VERSION 5.8 ;
BUSBITCHARS "[]" ;
DIVIDERCHAR "/" ;
UNITS
    DATABASE MICRONS 1000 ;
END UNITS

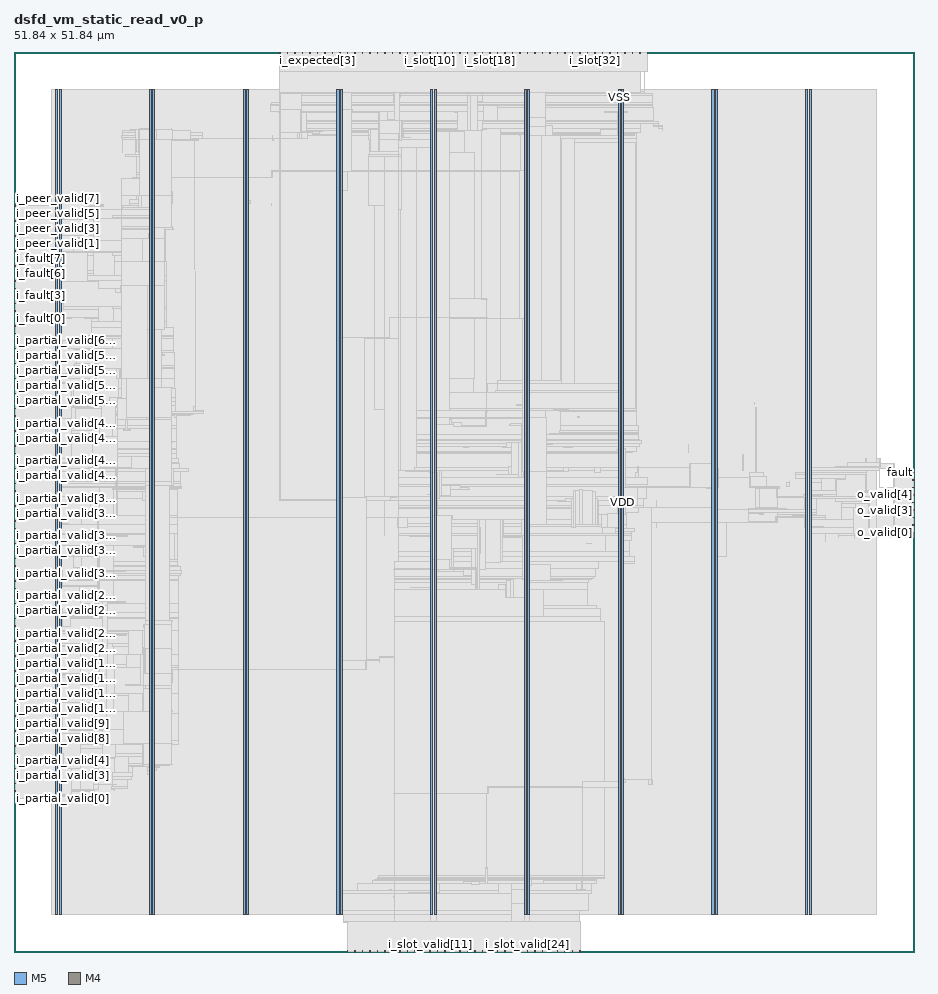
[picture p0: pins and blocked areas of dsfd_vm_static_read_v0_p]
MACRO dsfd_vm_static_read_v0_p
  FOREIGN dsfd_vm_static_read_v0_p 0 0 ;
  CLASS BLOCK ;
  SIZE 51.84 BY 51.84 ;
  PIN ck
    DIRECTION INPUT ;
    USE SIGNAL ;
    PORT
      LAYER M5 ;
        RECT  15.312 51.756 15.336 51.84 ;
    END
  END ck
  PIN fault
    DIRECTION OUTPUT ;
    USE SIGNAL ;
    PORT
      LAYER M4 ;
        RECT  51.756 27.6 51.84 27.624 ;
    END
  END fault
  PIN i_expected[0]
    DIRECTION INPUT ;
    USE SIGNAL ;
    PORT
      LAYER M5 ;
        RECT  16.176 51.756 16.2 51.84 ;
    END
  END i_expected[0]
  PIN i_expected[1]
    DIRECTION INPUT ;
    USE SIGNAL ;
    PORT
      LAYER M5 ;
        RECT  16.608 51.756 16.632 51.84 ;
    END
  END i_expected[1]
  PIN i_expected[2]
    DIRECTION INPUT ;
    USE SIGNAL ;
    PORT
      LAYER M5 ;
        RECT  17.04 51.756 17.064 51.84 ;
    END
  END i_expected[2]
  PIN i_expected[3]
    DIRECTION INPUT ;
    USE SIGNAL ;
    PORT
      LAYER M5 ;
        RECT  17.472 51.756 17.496 51.84 ;
    END
  END i_expected[3]
  PIN i_expected[4]
    DIRECTION INPUT ;
    USE SIGNAL ;
    PORT
      LAYER M5 ;
        RECT  17.904 51.756 17.928 51.84 ;
    END
  END i_expected[4]
  PIN i_expected[5]
    DIRECTION INPUT ;
    USE SIGNAL ;
    PORT
      LAYER M5 ;
        RECT  18.336 51.756 18.36 51.84 ;
    END
  END i_expected[5]
  PIN i_expected[6]
    DIRECTION INPUT ;
    USE SIGNAL ;
    PORT
      LAYER M5 ;
        RECT  18.768 51.756 18.792 51.84 ;
    END
  END i_expected[6]
  PIN i_expected[7]
    DIRECTION INPUT ;
    USE SIGNAL ;
    PORT
      LAYER M5 ;
        RECT  19.2 51.756 19.224 51.84 ;
    END
  END i_expected[7]
  PIN i_fault[0]
    DIRECTION INPUT ;
    USE SIGNAL ;
    PORT
      LAYER M4 ;
        RECT  0 36.48 0.084 36.504 ;
    END
  END i_fault[0]
  PIN i_fault[1]
    DIRECTION INPUT ;
    USE SIGNAL ;
    PORT
      LAYER M4 ;
        RECT  0 36.912 0.084 36.936 ;
    END
  END i_fault[1]
  PIN i_fault[2]
    DIRECTION INPUT ;
    USE SIGNAL ;
    PORT
      LAYER M4 ;
        RECT  0 37.344 0.084 37.368 ;
    END
  END i_fault[2]
  PIN i_fault[3]
    DIRECTION INPUT ;
    USE SIGNAL ;
    PORT
      LAYER M4 ;
        RECT  0 37.776 0.084 37.8 ;
    END
  END i_fault[3]
  PIN i_fault[4]
    DIRECTION INPUT ;
    USE SIGNAL ;
    PORT
      LAYER M4 ;
        RECT  0 38.208 0.084 38.232 ;
    END
  END i_fault[4]
  PIN i_fault[5]
    DIRECTION INPUT ;
    USE SIGNAL ;
    PORT
      LAYER M4 ;
        RECT  0 38.64 0.084 38.664 ;
    END
  END i_fault[5]
  PIN i_fault[6]
    DIRECTION INPUT ;
    USE SIGNAL ;
    PORT
      LAYER M4 ;
        RECT  0 39.072 0.084 39.096 ;
    END
  END i_fault[6]
  PIN i_fault[7]
    DIRECTION INPUT ;
    USE SIGNAL ;
    PORT
      LAYER M4 ;
        RECT  0 39.504 0.084 39.528 ;
    END
  END i_fault[7]
  PIN i_partial_valid[0]
    DIRECTION INPUT ;
    USE SIGNAL ;
    PORT
      LAYER M4 ;
        RECT  0 8.832 0.084 8.856 ;
    END
  END i_partial_valid[0]
  PIN i_partial_valid[10]
    DIRECTION INPUT ;
    USE SIGNAL ;
    PORT
      LAYER M4 ;
        RECT  0 13.152 0.084 13.176 ;
    END
  END i_partial_valid[10]
  PIN i_partial_valid[11]
    DIRECTION INPUT ;
    USE SIGNAL ;
    PORT
      LAYER M4 ;
        RECT  0 13.584 0.084 13.608 ;
    END
  END i_partial_valid[11]
  PIN i_partial_valid[12]
    DIRECTION INPUT ;
    USE SIGNAL ;
    PORT
      LAYER M4 ;
        RECT  0 14.016 0.084 14.04 ;
    END
  END i_partial_valid[12]
  PIN i_partial_valid[13]
    DIRECTION INPUT ;
    USE SIGNAL ;
    PORT
      LAYER M4 ;
        RECT  0 14.448 0.084 14.472 ;
    END
  END i_partial_valid[13]
  PIN i_partial_valid[14]
    DIRECTION INPUT ;
    USE SIGNAL ;
    PORT
      LAYER M4 ;
        RECT  0 14.88 0.084 14.904 ;
    END
  END i_partial_valid[14]
  PIN i_partial_valid[15]
    DIRECTION INPUT ;
    USE SIGNAL ;
    PORT
      LAYER M4 ;
        RECT  0 15.312 0.084 15.336 ;
    END
  END i_partial_valid[15]
  PIN i_partial_valid[16]
    DIRECTION INPUT ;
    USE SIGNAL ;
    PORT
      LAYER M4 ;
        RECT  0 15.744 0.084 15.768 ;
    END
  END i_partial_valid[16]
  PIN i_partial_valid[17]
    DIRECTION INPUT ;
    USE SIGNAL ;
    PORT
      LAYER M4 ;
        RECT  0 16.176 0.084 16.2 ;
    END
  END i_partial_valid[17]
  PIN i_partial_valid[18]
    DIRECTION INPUT ;
    USE SIGNAL ;
    PORT
      LAYER M4 ;
        RECT  0 16.608 0.084 16.632 ;
    END
  END i_partial_valid[18]
  PIN i_partial_valid[19]
    DIRECTION INPUT ;
    USE SIGNAL ;
    PORT
      LAYER M4 ;
        RECT  0 17.04 0.084 17.064 ;
    END
  END i_partial_valid[19]
  PIN i_partial_valid[1]
    DIRECTION INPUT ;
    USE SIGNAL ;
    PORT
      LAYER M4 ;
        RECT  0 9.264 0.084 9.288 ;
    END
  END i_partial_valid[1]
  PIN i_partial_valid[20]
    DIRECTION INPUT ;
    USE SIGNAL ;
    PORT
      LAYER M4 ;
        RECT  0 17.472 0.084 17.496 ;
    END
  END i_partial_valid[20]
  PIN i_partial_valid[21]
    DIRECTION INPUT ;
    USE SIGNAL ;
    PORT
      LAYER M4 ;
        RECT  0 17.904 0.084 17.928 ;
    END
  END i_partial_valid[21]
  PIN i_partial_valid[22]
    DIRECTION INPUT ;
    USE SIGNAL ;
    PORT
      LAYER M4 ;
        RECT  0 18.336 0.084 18.36 ;
    END
  END i_partial_valid[22]
  PIN i_partial_valid[23]
    DIRECTION INPUT ;
    USE SIGNAL ;
    PORT
      LAYER M4 ;
        RECT  0 18.768 0.084 18.792 ;
    END
  END i_partial_valid[23]
  PIN i_partial_valid[24]
    DIRECTION INPUT ;
    USE SIGNAL ;
    PORT
      LAYER M4 ;
        RECT  0 19.2 0.084 19.224 ;
    END
  END i_partial_valid[24]
  PIN i_partial_valid[25]
    DIRECTION INPUT ;
    USE SIGNAL ;
    PORT
      LAYER M4 ;
        RECT  0 19.632 0.084 19.656 ;
    END
  END i_partial_valid[25]
  PIN i_partial_valid[26]
    DIRECTION INPUT ;
    USE SIGNAL ;
    PORT
      LAYER M4 ;
        RECT  0 20.064 0.084 20.088 ;
    END
  END i_partial_valid[26]
  PIN i_partial_valid[27]
    DIRECTION INPUT ;
    USE SIGNAL ;
    PORT
      LAYER M4 ;
        RECT  0 20.496 0.084 20.52 ;
    END
  END i_partial_valid[27]
  PIN i_partial_valid[28]
    DIRECTION INPUT ;
    USE SIGNAL ;
    PORT
      LAYER M4 ;
        RECT  0 20.928 0.084 20.952 ;
    END
  END i_partial_valid[28]
  PIN i_partial_valid[29]
    DIRECTION INPUT ;
    USE SIGNAL ;
    PORT
      LAYER M4 ;
        RECT  0 21.36 0.084 21.384 ;
    END
  END i_partial_valid[29]
  PIN i_partial_valid[2]
    DIRECTION INPUT ;
    USE SIGNAL ;
    PORT
      LAYER M4 ;
        RECT  0 9.696 0.084 9.72 ;
    END
  END i_partial_valid[2]
  PIN i_partial_valid[30]
    DIRECTION INPUT ;
    USE SIGNAL ;
    PORT
      LAYER M4 ;
        RECT  0 21.792 0.084 21.816 ;
    END
  END i_partial_valid[30]
  PIN i_partial_valid[31]
    DIRECTION INPUT ;
    USE SIGNAL ;
    PORT
      LAYER M4 ;
        RECT  0 22.224 0.084 22.248 ;
    END
  END i_partial_valid[31]
  PIN i_partial_valid[32]
    DIRECTION INPUT ;
    USE SIGNAL ;
    PORT
      LAYER M4 ;
        RECT  0 22.656 0.084 22.68 ;
    END
  END i_partial_valid[32]
  PIN i_partial_valid[33]
    DIRECTION INPUT ;
    USE SIGNAL ;
    PORT
      LAYER M4 ;
        RECT  0 23.088 0.084 23.112 ;
    END
  END i_partial_valid[33]
  PIN i_partial_valid[34]
    DIRECTION INPUT ;
    USE SIGNAL ;
    PORT
      LAYER M4 ;
        RECT  0 23.52 0.084 23.544 ;
    END
  END i_partial_valid[34]
  PIN i_partial_valid[35]
    DIRECTION INPUT ;
    USE SIGNAL ;
    PORT
      LAYER M4 ;
        RECT  0 23.952 0.084 23.976 ;
    END
  END i_partial_valid[35]
  PIN i_partial_valid[36]
    DIRECTION INPUT ;
    USE SIGNAL ;
    PORT
      LAYER M4 ;
        RECT  0 24.384 0.084 24.408 ;
    END
  END i_partial_valid[36]
  PIN i_partial_valid[37]
    DIRECTION INPUT ;
    USE SIGNAL ;
    PORT
      LAYER M4 ;
        RECT  0 24.816 0.084 24.84 ;
    END
  END i_partial_valid[37]
  PIN i_partial_valid[38]
    DIRECTION INPUT ;
    USE SIGNAL ;
    PORT
      LAYER M4 ;
        RECT  0 25.248 0.084 25.272 ;
    END
  END i_partial_valid[38]
  PIN i_partial_valid[39]
    DIRECTION INPUT ;
    USE SIGNAL ;
    PORT
      LAYER M4 ;
        RECT  0 25.68 0.084 25.704 ;
    END
  END i_partial_valid[39]
  PIN i_partial_valid[3]
    DIRECTION INPUT ;
    USE SIGNAL ;
    PORT
      LAYER M4 ;
        RECT  0 10.128 0.084 10.152 ;
    END
  END i_partial_valid[3]
  PIN i_partial_valid[40]
    DIRECTION INPUT ;
    USE SIGNAL ;
    PORT
      LAYER M4 ;
        RECT  0 26.112 0.084 26.136 ;
    END
  END i_partial_valid[40]
  PIN i_partial_valid[41]
    DIRECTION INPUT ;
    USE SIGNAL ;
    PORT
      LAYER M4 ;
        RECT  0 26.544 0.084 26.568 ;
    END
  END i_partial_valid[41]
  PIN i_partial_valid[42]
    DIRECTION INPUT ;
    USE SIGNAL ;
    PORT
      LAYER M4 ;
        RECT  0 26.976 0.084 27 ;
    END
  END i_partial_valid[42]
  PIN i_partial_valid[43]
    DIRECTION INPUT ;
    USE SIGNAL ;
    PORT
      LAYER M4 ;
        RECT  0 27.408 0.084 27.432 ;
    END
  END i_partial_valid[43]
  PIN i_partial_valid[44]
    DIRECTION INPUT ;
    USE SIGNAL ;
    PORT
      LAYER M4 ;
        RECT  0 27.84 0.084 27.864 ;
    END
  END i_partial_valid[44]
  PIN i_partial_valid[45]
    DIRECTION INPUT ;
    USE SIGNAL ;
    PORT
      LAYER M4 ;
        RECT  0 28.272 0.084 28.296 ;
    END
  END i_partial_valid[45]
  PIN i_partial_valid[46]
    DIRECTION INPUT ;
    USE SIGNAL ;
    PORT
      LAYER M4 ;
        RECT  0 28.704 0.084 28.728 ;
    END
  END i_partial_valid[46]
  PIN i_partial_valid[47]
    DIRECTION INPUT ;
    USE SIGNAL ;
    PORT
      LAYER M4 ;
        RECT  0 29.136 0.084 29.16 ;
    END
  END i_partial_valid[47]
  PIN i_partial_valid[48]
    DIRECTION INPUT ;
    USE SIGNAL ;
    PORT
      LAYER M4 ;
        RECT  0 29.568 0.084 29.592 ;
    END
  END i_partial_valid[48]
  PIN i_partial_valid[49]
    DIRECTION INPUT ;
    USE SIGNAL ;
    PORT
      LAYER M4 ;
        RECT  0 30 0.084 30.024 ;
    END
  END i_partial_valid[49]
  PIN i_partial_valid[4]
    DIRECTION INPUT ;
    USE SIGNAL ;
    PORT
      LAYER M4 ;
        RECT  0 10.56 0.084 10.584 ;
    END
  END i_partial_valid[4]
  PIN i_partial_valid[50]
    DIRECTION INPUT ;
    USE SIGNAL ;
    PORT
      LAYER M4 ;
        RECT  0 30.432 0.084 30.456 ;
    END
  END i_partial_valid[50]
  PIN i_partial_valid[51]
    DIRECTION INPUT ;
    USE SIGNAL ;
    PORT
      LAYER M4 ;
        RECT  0 30.864 0.084 30.888 ;
    END
  END i_partial_valid[51]
  PIN i_partial_valid[52]
    DIRECTION INPUT ;
    USE SIGNAL ;
    PORT
      LAYER M4 ;
        RECT  0 31.296 0.084 31.32 ;
    END
  END i_partial_valid[52]
  PIN i_partial_valid[53]
    DIRECTION INPUT ;
    USE SIGNAL ;
    PORT
      LAYER M4 ;
        RECT  0 31.728 0.084 31.752 ;
    END
  END i_partial_valid[53]
  PIN i_partial_valid[54]
    DIRECTION INPUT ;
    USE SIGNAL ;
    PORT
      LAYER M4 ;
        RECT  0 32.16 0.084 32.184 ;
    END
  END i_partial_valid[54]
  PIN i_partial_valid[55]
    DIRECTION INPUT ;
    USE SIGNAL ;
    PORT
      LAYER M4 ;
        RECT  0 32.592 0.084 32.616 ;
    END
  END i_partial_valid[55]
  PIN i_partial_valid[56]
    DIRECTION INPUT ;
    USE SIGNAL ;
    PORT
      LAYER M4 ;
        RECT  0 33.024 0.084 33.048 ;
    END
  END i_partial_valid[56]
  PIN i_partial_valid[57]
    DIRECTION INPUT ;
    USE SIGNAL ;
    PORT
      LAYER M4 ;
        RECT  0 33.456 0.084 33.48 ;
    END
  END i_partial_valid[57]
  PIN i_partial_valid[58]
    DIRECTION INPUT ;
    USE SIGNAL ;
    PORT
      LAYER M4 ;
        RECT  0 33.888 0.084 33.912 ;
    END
  END i_partial_valid[58]
  PIN i_partial_valid[59]
    DIRECTION INPUT ;
    USE SIGNAL ;
    PORT
      LAYER M4 ;
        RECT  0 34.32 0.084 34.344 ;
    END
  END i_partial_valid[59]
  PIN i_partial_valid[5]
    DIRECTION INPUT ;
    USE SIGNAL ;
    PORT
      LAYER M4 ;
        RECT  0 10.992 0.084 11.016 ;
    END
  END i_partial_valid[5]
  PIN i_partial_valid[60]
    DIRECTION INPUT ;
    USE SIGNAL ;
    PORT
      LAYER M4 ;
        RECT  0 34.752 0.084 34.776 ;
    END
  END i_partial_valid[60]
  PIN i_partial_valid[61]
    DIRECTION INPUT ;
    USE SIGNAL ;
    PORT
      LAYER M4 ;
        RECT  0 35.184 0.084 35.208 ;
    END
  END i_partial_valid[61]
  PIN i_partial_valid[62]
    DIRECTION INPUT ;
    USE SIGNAL ;
    PORT
      LAYER M4 ;
        RECT  0 35.616 0.084 35.64 ;
    END
  END i_partial_valid[62]
  PIN i_partial_valid[63]
    DIRECTION INPUT ;
    USE SIGNAL ;
    PORT
      LAYER M4 ;
        RECT  0 36.048 0.084 36.072 ;
    END
  END i_partial_valid[63]
  PIN i_partial_valid[6]
    DIRECTION INPUT ;
    USE SIGNAL ;
    PORT
      LAYER M4 ;
        RECT  0 11.424 0.084 11.448 ;
    END
  END i_partial_valid[6]
  PIN i_partial_valid[7]
    DIRECTION INPUT ;
    USE SIGNAL ;
    PORT
      LAYER M4 ;
        RECT  0 11.856 0.084 11.88 ;
    END
  END i_partial_valid[7]
  PIN i_partial_valid[8]
    DIRECTION INPUT ;
    USE SIGNAL ;
    PORT
      LAYER M4 ;
        RECT  0 12.288 0.084 12.312 ;
    END
  END i_partial_valid[8]
  PIN i_partial_valid[9]
    DIRECTION INPUT ;
    USE SIGNAL ;
    PORT
      LAYER M4 ;
        RECT  0 12.72 0.084 12.744 ;
    END
  END i_partial_valid[9]
  PIN i_peer_valid[0]
    DIRECTION INPUT ;
    USE SIGNAL ;
    PORT
      LAYER M4 ;
        RECT  0 39.936 0.084 39.96 ;
    END
  END i_peer_valid[0]
  PIN i_peer_valid[1]
    DIRECTION INPUT ;
    USE SIGNAL ;
    PORT
      LAYER M4 ;
        RECT  0 40.368 0.084 40.392 ;
    END
  END i_peer_valid[1]
  PIN i_peer_valid[2]
    DIRECTION INPUT ;
    USE SIGNAL ;
    PORT
      LAYER M4 ;
        RECT  0 40.8 0.084 40.824 ;
    END
  END i_peer_valid[2]
  PIN i_peer_valid[3]
    DIRECTION INPUT ;
    USE SIGNAL ;
    PORT
      LAYER M4 ;
        RECT  0 41.232 0.084 41.256 ;
    END
  END i_peer_valid[3]
  PIN i_peer_valid[4]
    DIRECTION INPUT ;
    USE SIGNAL ;
    PORT
      LAYER M4 ;
        RECT  0 41.664 0.084 41.688 ;
    END
  END i_peer_valid[4]
  PIN i_peer_valid[5]
    DIRECTION INPUT ;
    USE SIGNAL ;
    PORT
      LAYER M4 ;
        RECT  0 42.096 0.084 42.12 ;
    END
  END i_peer_valid[5]
  PIN i_peer_valid[6]
    DIRECTION INPUT ;
    USE SIGNAL ;
    PORT
      LAYER M4 ;
        RECT  0 42.528 0.084 42.552 ;
    END
  END i_peer_valid[6]
  PIN i_peer_valid[7]
    DIRECTION INPUT ;
    USE SIGNAL ;
    PORT
      LAYER M4 ;
        RECT  0 42.96 0.084 42.984 ;
    END
  END i_peer_valid[7]
  PIN i_slot[0]
    DIRECTION INPUT ;
    USE SIGNAL ;
    PORT
      LAYER M5 ;
        RECT  19.632 51.756 19.656 51.84 ;
    END
  END i_slot[0]
  PIN i_slot[10]
    DIRECTION INPUT ;
    USE SIGNAL ;
    PORT
      LAYER M5 ;
        RECT  23.952 51.756 23.976 51.84 ;
    END
  END i_slot[10]
  PIN i_slot[11]
    DIRECTION INPUT ;
    USE SIGNAL ;
    PORT
      LAYER M5 ;
        RECT  24.384 51.756 24.408 51.84 ;
    END
  END i_slot[11]
  PIN i_slot[12]
    DIRECTION INPUT ;
    USE SIGNAL ;
    PORT
      LAYER M5 ;
        RECT  24.816 51.756 24.84 51.84 ;
    END
  END i_slot[12]
  PIN i_slot[13]
    DIRECTION INPUT ;
    USE SIGNAL ;
    PORT
      LAYER M5 ;
        RECT  25.248 51.756 25.272 51.84 ;
    END
  END i_slot[13]
  PIN i_slot[14]
    DIRECTION INPUT ;
    USE SIGNAL ;
    PORT
      LAYER M5 ;
        RECT  25.68 51.756 25.704 51.84 ;
    END
  END i_slot[14]
  PIN i_slot[15]
    DIRECTION INPUT ;
    USE SIGNAL ;
    PORT
      LAYER M5 ;
        RECT  26.112 51.756 26.136 51.84 ;
    END
  END i_slot[15]
  PIN i_slot[16]
    DIRECTION INPUT ;
    USE SIGNAL ;
    PORT
      LAYER M5 ;
        RECT  26.544 51.756 26.568 51.84 ;
    END
  END i_slot[16]
  PIN i_slot[17]
    DIRECTION INPUT ;
    USE SIGNAL ;
    PORT
      LAYER M5 ;
        RECT  26.976 51.756 27 51.84 ;
    END
  END i_slot[17]
  PIN i_slot[18]
    DIRECTION INPUT ;
    USE SIGNAL ;
    PORT
      LAYER M5 ;
        RECT  27.408 51.756 27.432 51.84 ;
    END
  END i_slot[18]
  PIN i_slot[19]
    DIRECTION INPUT ;
    USE SIGNAL ;
    PORT
      LAYER M5 ;
        RECT  27.84 51.756 27.864 51.84 ;
    END
  END i_slot[19]
  PIN i_slot[1]
    DIRECTION INPUT ;
    USE SIGNAL ;
    PORT
      LAYER M5 ;
        RECT  20.064 51.756 20.088 51.84 ;
    END
  END i_slot[1]
  PIN i_slot[20]
    DIRECTION INPUT ;
    USE SIGNAL ;
    PORT
      LAYER M5 ;
        RECT  28.272 51.756 28.296 51.84 ;
    END
  END i_slot[20]
  PIN i_slot[21]
    DIRECTION INPUT ;
    USE SIGNAL ;
    PORT
      LAYER M5 ;
        RECT  28.704 51.756 28.728 51.84 ;
    END
  END i_slot[21]
  PIN i_slot[22]
    DIRECTION INPUT ;
    USE SIGNAL ;
    PORT
      LAYER M5 ;
        RECT  29.136 51.756 29.16 51.84 ;
    END
  END i_slot[22]
  PIN i_slot[23]
    DIRECTION INPUT ;
    USE SIGNAL ;
    PORT
      LAYER M5 ;
        RECT  29.568 51.756 29.592 51.84 ;
    END
  END i_slot[23]
  PIN i_slot[24]
    DIRECTION INPUT ;
    USE SIGNAL ;
    PORT
      LAYER M5 ;
        RECT  30 51.756 30.024 51.84 ;
    END
  END i_slot[24]
  PIN i_slot[25]
    DIRECTION INPUT ;
    USE SIGNAL ;
    PORT
      LAYER M5 ;
        RECT  30.432 51.756 30.456 51.84 ;
    END
  END i_slot[25]
  PIN i_slot[26]
    DIRECTION INPUT ;
    USE SIGNAL ;
    PORT
      LAYER M5 ;
        RECT  30.864 51.756 30.888 51.84 ;
    END
  END i_slot[26]
  PIN i_slot[27]
    DIRECTION INPUT ;
    USE SIGNAL ;
    PORT
      LAYER M5 ;
        RECT  31.296 51.756 31.32 51.84 ;
    END
  END i_slot[27]
  PIN i_slot[28]
    DIRECTION INPUT ;
    USE SIGNAL ;
    PORT
      LAYER M5 ;
        RECT  31.728 51.756 31.752 51.84 ;
    END
  END i_slot[28]
  PIN i_slot[29]
    DIRECTION INPUT ;
    USE SIGNAL ;
    PORT
      LAYER M5 ;
        RECT  32.16 51.756 32.184 51.84 ;
    END
  END i_slot[29]
  PIN i_slot[2]
    DIRECTION INPUT ;
    USE SIGNAL ;
    PORT
      LAYER M5 ;
        RECT  20.496 51.756 20.52 51.84 ;
    END
  END i_slot[2]
  PIN i_slot[30]
    DIRECTION INPUT ;
    USE SIGNAL ;
    PORT
      LAYER M5 ;
        RECT  32.592 51.756 32.616 51.84 ;
    END
  END i_slot[30]
  PIN i_slot[31]
    DIRECTION INPUT ;
    USE SIGNAL ;
    PORT
      LAYER M5 ;
        RECT  33.024 51.756 33.048 51.84 ;
    END
  END i_slot[31]
  PIN i_slot[32]
    DIRECTION INPUT ;
    USE SIGNAL ;
    PORT
      LAYER M5 ;
        RECT  33.456 51.756 33.48 51.84 ;
    END
  END i_slot[32]
  PIN i_slot[33]
    DIRECTION INPUT ;
    USE SIGNAL ;
    PORT
      LAYER M5 ;
        RECT  33.888 51.756 33.912 51.84 ;
    END
  END i_slot[33]
  PIN i_slot[34]
    DIRECTION INPUT ;
    USE SIGNAL ;
    PORT
      LAYER M5 ;
        RECT  34.32 51.756 34.344 51.84 ;
    END
  END i_slot[34]
  PIN i_slot[35]
    DIRECTION INPUT ;
    USE SIGNAL ;
    PORT
      LAYER M5 ;
        RECT  34.752 51.756 34.776 51.84 ;
    END
  END i_slot[35]
  PIN i_slot[36]
    DIRECTION INPUT ;
    USE SIGNAL ;
    PORT
      LAYER M5 ;
        RECT  35.184 51.756 35.208 51.84 ;
    END
  END i_slot[36]
  PIN i_slot[37]
    DIRECTION INPUT ;
    USE SIGNAL ;
    PORT
      LAYER M5 ;
        RECT  35.616 51.756 35.64 51.84 ;
    END
  END i_slot[37]
  PIN i_slot[38]
    DIRECTION INPUT ;
    USE SIGNAL ;
    PORT
      LAYER M5 ;
        RECT  36.048 51.756 36.072 51.84 ;
    END
  END i_slot[38]
  PIN i_slot[39]
    DIRECTION INPUT ;
    USE SIGNAL ;
    PORT
      LAYER M5 ;
        RECT  36.48 51.756 36.504 51.84 ;
    END
  END i_slot[39]
  PIN i_slot[3]
    DIRECTION INPUT ;
    USE SIGNAL ;
    PORT
      LAYER M5 ;
        RECT  20.928 51.756 20.952 51.84 ;
    END
  END i_slot[3]
  PIN i_slot[4]
    DIRECTION INPUT ;
    USE SIGNAL ;
    PORT
      LAYER M5 ;
        RECT  21.36 51.756 21.384 51.84 ;
    END
  END i_slot[4]
  PIN i_slot[5]
    DIRECTION INPUT ;
    USE SIGNAL ;
    PORT
      LAYER M5 ;
        RECT  21.792 51.756 21.816 51.84 ;
    END
  END i_slot[5]
  PIN i_slot[6]
    DIRECTION INPUT ;
    USE SIGNAL ;
    PORT
      LAYER M5 ;
        RECT  22.224 51.756 22.248 51.84 ;
    END
  END i_slot[6]
  PIN i_slot[7]
    DIRECTION INPUT ;
    USE SIGNAL ;
    PORT
      LAYER M5 ;
        RECT  22.656 51.756 22.68 51.84 ;
    END
  END i_slot[7]
  PIN i_slot[8]
    DIRECTION INPUT ;
    USE SIGNAL ;
    PORT
      LAYER M5 ;
        RECT  23.088 51.756 23.112 51.84 ;
    END
  END i_slot[8]
  PIN i_slot[9]
    DIRECTION INPUT ;
    USE SIGNAL ;
    PORT
      LAYER M5 ;
        RECT  23.52 51.756 23.544 51.84 ;
    END
  END i_slot[9]
  PIN i_slot_valid[0]
    DIRECTION INPUT ;
    USE SIGNAL ;
    PORT
      LAYER M5 ;
        RECT  19.2 0 19.224 0.084 ;
    END
  END i_slot_valid[0]
  PIN i_slot_valid[10]
    DIRECTION INPUT ;
    USE SIGNAL ;
    PORT
      LAYER M5 ;
        RECT  23.52 0 23.544 0.084 ;
    END
  END i_slot_valid[10]
  PIN i_slot_valid[11]
    DIRECTION INPUT ;
    USE SIGNAL ;
    PORT
      LAYER M5 ;
        RECT  23.952 0 23.976 0.084 ;
    END
  END i_slot_valid[11]
  PIN i_slot_valid[12]
    DIRECTION INPUT ;
    USE SIGNAL ;
    PORT
      LAYER M5 ;
        RECT  24.384 0 24.408 0.084 ;
    END
  END i_slot_valid[12]
  PIN i_slot_valid[13]
    DIRECTION INPUT ;
    USE SIGNAL ;
    PORT
      LAYER M5 ;
        RECT  24.816 0 24.84 0.084 ;
    END
  END i_slot_valid[13]
  PIN i_slot_valid[14]
    DIRECTION INPUT ;
    USE SIGNAL ;
    PORT
      LAYER M5 ;
        RECT  25.248 0 25.272 0.084 ;
    END
  END i_slot_valid[14]
  PIN i_slot_valid[15]
    DIRECTION INPUT ;
    USE SIGNAL ;
    PORT
      LAYER M5 ;
        RECT  25.68 0 25.704 0.084 ;
    END
  END i_slot_valid[15]
  PIN i_slot_valid[16]
    DIRECTION INPUT ;
    USE SIGNAL ;
    PORT
      LAYER M5 ;
        RECT  26.112 0 26.136 0.084 ;
    END
  END i_slot_valid[16]
  PIN i_slot_valid[17]
    DIRECTION INPUT ;
    USE SIGNAL ;
    PORT
      LAYER M5 ;
        RECT  26.544 0 26.568 0.084 ;
    END
  END i_slot_valid[17]
  PIN i_slot_valid[18]
    DIRECTION INPUT ;
    USE SIGNAL ;
    PORT
      LAYER M5 ;
        RECT  26.976 0 27 0.084 ;
    END
  END i_slot_valid[18]
  PIN i_slot_valid[19]
    DIRECTION INPUT ;
    USE SIGNAL ;
    PORT
      LAYER M5 ;
        RECT  27.408 0 27.432 0.084 ;
    END
  END i_slot_valid[19]
  PIN i_slot_valid[1]
    DIRECTION INPUT ;
    USE SIGNAL ;
    PORT
      LAYER M5 ;
        RECT  19.632 0 19.656 0.084 ;
    END
  END i_slot_valid[1]
  PIN i_slot_valid[20]
    DIRECTION INPUT ;
    USE SIGNAL ;
    PORT
      LAYER M5 ;
        RECT  27.84 0 27.864 0.084 ;
    END
  END i_slot_valid[20]
  PIN i_slot_valid[21]
    DIRECTION INPUT ;
    USE SIGNAL ;
    PORT
      LAYER M5 ;
        RECT  28.272 0 28.296 0.084 ;
    END
  END i_slot_valid[21]
  PIN i_slot_valid[22]
    DIRECTION INPUT ;
    USE SIGNAL ;
    PORT
      LAYER M5 ;
        RECT  28.704 0 28.728 0.084 ;
    END
  END i_slot_valid[22]
  PIN i_slot_valid[23]
    DIRECTION INPUT ;
    USE SIGNAL ;
    PORT
      LAYER M5 ;
        RECT  29.136 0 29.16 0.084 ;
    END
  END i_slot_valid[23]
  PIN i_slot_valid[24]
    DIRECTION INPUT ;
    USE SIGNAL ;
    PORT
      LAYER M5 ;
        RECT  29.568 0 29.592 0.084 ;
    END
  END i_slot_valid[24]
  PIN i_slot_valid[25]
    DIRECTION INPUT ;
    USE SIGNAL ;
    PORT
      LAYER M5 ;
        RECT  30 0 30.024 0.084 ;
    END
  END i_slot_valid[25]
  PIN i_slot_valid[26]
    DIRECTION INPUT ;
    USE SIGNAL ;
    PORT
      LAYER M5 ;
        RECT  30.432 0 30.456 0.084 ;
    END
  END i_slot_valid[26]
  PIN i_slot_valid[27]
    DIRECTION INPUT ;
    USE SIGNAL ;
    PORT
      LAYER M5 ;
        RECT  30.864 0 30.888 0.084 ;
    END
  END i_slot_valid[27]
  PIN i_slot_valid[28]
    DIRECTION INPUT ;
    USE SIGNAL ;
    PORT
      LAYER M5 ;
        RECT  31.296 0 31.32 0.084 ;
    END
  END i_slot_valid[28]
  PIN i_slot_valid[29]
    DIRECTION INPUT ;
    USE SIGNAL ;
    PORT
      LAYER M5 ;
        RECT  31.728 0 31.752 0.084 ;
    END
  END i_slot_valid[29]
  PIN i_slot_valid[2]
    DIRECTION INPUT ;
    USE SIGNAL ;
    PORT
      LAYER M5 ;
        RECT  20.064 0 20.088 0.084 ;
    END
  END i_slot_valid[2]
  PIN i_slot_valid[30]
    DIRECTION INPUT ;
    USE SIGNAL ;
    PORT
      LAYER M5 ;
        RECT  32.16 0 32.184 0.084 ;
    END
  END i_slot_valid[30]
  PIN i_slot_valid[31]
    DIRECTION INPUT ;
    USE SIGNAL ;
    PORT
      LAYER M5 ;
        RECT  32.592 0 32.616 0.084 ;
    END
  END i_slot_valid[31]
  PIN i_slot_valid[3]
    DIRECTION INPUT ;
    USE SIGNAL ;
    PORT
      LAYER M5 ;
        RECT  20.496 0 20.52 0.084 ;
    END
  END i_slot_valid[3]
  PIN i_slot_valid[4]
    DIRECTION INPUT ;
    USE SIGNAL ;
    PORT
      LAYER M5 ;
        RECT  20.928 0 20.952 0.084 ;
    END
  END i_slot_valid[4]
  PIN i_slot_valid[5]
    DIRECTION INPUT ;
    USE SIGNAL ;
    PORT
      LAYER M5 ;
        RECT  21.36 0 21.384 0.084 ;
    END
  END i_slot_valid[5]
  PIN i_slot_valid[6]
    DIRECTION INPUT ;
    USE SIGNAL ;
    PORT
      LAYER M5 ;
        RECT  21.792 0 21.816 0.084 ;
    END
  END i_slot_valid[6]
  PIN i_slot_valid[7]
    DIRECTION INPUT ;
    USE SIGNAL ;
    PORT
      LAYER M5 ;
        RECT  22.224 0 22.248 0.084 ;
    END
  END i_slot_valid[7]
  PIN i_slot_valid[8]
    DIRECTION INPUT ;
    USE SIGNAL ;
    PORT
      LAYER M5 ;
        RECT  22.656 0 22.68 0.084 ;
    END
  END i_slot_valid[8]
  PIN i_slot_valid[9]
    DIRECTION INPUT ;
    USE SIGNAL ;
    PORT
      LAYER M5 ;
        RECT  23.088 0 23.112 0.084 ;
    END
  END i_slot_valid[9]
  PIN o_valid[0]
    DIRECTION OUTPUT ;
    USE SIGNAL ;
    PORT
      LAYER M4 ;
        RECT  51.756 24.144 51.84 24.168 ;
    END
  END o_valid[0]
  PIN o_valid[1]
    DIRECTION OUTPUT ;
    USE SIGNAL ;
    PORT
      LAYER M4 ;
        RECT  51.756 24.576 51.84 24.6 ;
    END
  END o_valid[1]
  PIN o_valid[2]
    DIRECTION OUTPUT ;
    USE SIGNAL ;
    PORT
      LAYER M4 ;
        RECT  51.756 25.008 51.84 25.032 ;
    END
  END o_valid[2]
  PIN o_valid[3]
    DIRECTION OUTPUT ;
    USE SIGNAL ;
    PORT
      LAYER M4 ;
        RECT  51.756 25.44 51.84 25.464 ;
    END
  END o_valid[3]
  PIN o_valid[4]
    DIRECTION OUTPUT ;
    USE SIGNAL ;
    PORT
      LAYER M4 ;
        RECT  51.756 25.872 51.84 25.896 ;
    END
  END o_valid[4]
  PIN o_valid[5]
    DIRECTION OUTPUT ;
    USE SIGNAL ;
    PORT
      LAYER M4 ;
        RECT  51.756 26.304 51.84 26.328 ;
    END
  END o_valid[5]
  PIN o_valid[6]
    DIRECTION OUTPUT ;
    USE SIGNAL ;
    PORT
      LAYER M4 ;
        RECT  51.756 26.736 51.84 26.76 ;
    END
  END o_valid[6]
  PIN o_valid[7]
    DIRECTION OUTPUT ;
    USE SIGNAL ;
    PORT
      LAYER M4 ;
        RECT  51.756 27.168 51.84 27.192 ;
    END
  END o_valid[7]
  PIN rst_n
    DIRECTION INPUT ;
    USE SIGNAL ;
    PORT
      LAYER M5 ;
        RECT  15.744 51.756 15.768 51.84 ;
    END
  END rst_n
  PIN VDD
    DIRECTION INOUT ;
    USE POWER ;
    PORT
      LAYER M5 ;
        RECT  45.792 2.151 45.912 49.689 ;
        RECT  40.392 2.151 40.512 49.689 ;
        RECT  34.992 2.151 35.112 49.689 ;
        RECT  29.592 2.151 29.712 49.689 ;
        RECT  24.192 2.151 24.312 49.689 ;
        RECT  18.792 2.151 18.912 49.689 ;
        RECT  13.392 2.151 13.512 49.689 ;
        RECT  7.992 2.151 8.112 49.689 ;
        RECT  2.592 2.151 2.712 49.689 ;
    END
  END VDD
  PIN VSS
    DIRECTION INOUT ;
    USE GROUND ;
    PORT
      LAYER M5 ;
        RECT  45.6 2.137 45.72 49.703 ;
        RECT  40.2 2.137 40.32 49.703 ;
        RECT  34.8 2.137 34.92 49.703 ;
        RECT  29.4 2.137 29.52 49.703 ;
        RECT  24 2.137 24.12 49.703 ;
        RECT  18.6 2.137 18.72 49.703 ;
        RECT  13.2 2.137 13.32 49.703 ;
        RECT  7.8 2.137 7.92 49.703 ;
        RECT  2.4 2.137 2.52 49.703 ;
    END
  END VSS
  # OT_OBS_CLOSED layer=M5 d_um=1.536 added=38
  OBS
    LAYER RVTN ;
     RECT  2.16 2.16 49.68 2.295 ;
     RECT  2.16 2.565 49.68 2.835 ;
     RECT  2.16 3.105 49.68 3.375 ;
     RECT  2.16 3.645 49.68 3.915 ;
     RECT  2.16 4.185 49.68 4.455 ;
     RECT  2.16 4.725 49.68 4.995 ;
     RECT  2.16 5.265 49.68 5.535 ;
     RECT  2.16 5.805 49.68 6.075 ;
     RECT  2.16 6.345 49.68 6.615 ;
     RECT  2.16 6.885 49.68 7.155 ;
     RECT  2.16 7.425 49.68 7.695 ;
     RECT  2.16 7.965 49.68 8.235 ;
     RECT  2.16 8.505 49.68 8.775 ;
     RECT  2.16 9.045 49.68 9.315 ;
     RECT  2.16 9.585 49.68 9.855 ;
     RECT  2.16 10.125 49.68 10.395 ;
     RECT  2.16 10.665 49.68 10.935 ;
     RECT  2.16 11.205 49.68 11.475 ;
     RECT  2.16 11.745 49.68 12.015 ;
     RECT  2.16 12.285 49.68 12.555 ;
     RECT  2.16 12.825 49.68 13.095 ;
     RECT  2.16 13.365 49.68 13.635 ;
     RECT  2.16 13.905 49.68 14.175 ;
     RECT  2.16 14.445 49.68 14.715 ;
     RECT  2.16 14.985 49.68 15.255 ;
     RECT  2.16 15.525 49.68 15.795 ;
     RECT  2.16 16.065 49.68 16.335 ;
     RECT  2.16 16.605 49.68 16.875 ;
     RECT  2.16 17.145 49.68 17.415 ;
     RECT  2.16 17.685 49.68 17.955 ;
     RECT  2.16 18.225 49.68 18.495 ;
     RECT  2.16 18.765 49.68 19.035 ;
     RECT  2.16 19.305 49.68 19.575 ;
     RECT  2.16 19.845 49.68 20.115 ;
     RECT  2.16 20.385 49.68 20.655 ;
     RECT  2.16 20.925 49.68 21.195 ;
     RECT  2.16 21.465 49.68 21.735 ;
     RECT  2.16 22.005 49.68 22.275 ;
     RECT  2.16 22.545 49.68 22.815 ;
     RECT  2.16 23.085 49.68 23.355 ;
     RECT  2.16 23.625 49.68 23.895 ;
     RECT  2.16 24.165 49.68 24.435 ;
     RECT  2.16 24.705 49.68 24.975 ;
     RECT  2.16 25.245 49.68 25.515 ;
     RECT  2.16 25.785 49.68 26.055 ;
     RECT  2.16 26.325 49.68 26.595 ;
     RECT  2.16 26.865 49.68 27.135 ;
     RECT  2.16 27.405 49.68 27.675 ;
     RECT  2.16 27.945 49.68 28.215 ;
     RECT  2.16 28.485 49.68 28.755 ;
     RECT  2.16 29.025 49.68 29.295 ;
     RECT  2.16 29.565 49.68 29.835 ;
     RECT  2.16 30.105 49.68 30.375 ;
     RECT  2.16 30.645 49.68 30.915 ;
     RECT  2.16 31.185 49.68 31.455 ;
     RECT  2.16 31.725 49.68 31.995 ;
     RECT  2.16 32.265 49.68 32.535 ;
     RECT  2.16 32.805 49.68 33.075 ;
     RECT  2.16 33.345 49.68 33.615 ;
     RECT  2.16 33.885 49.68 34.155 ;
     RECT  2.16 34.425 49.68 34.695 ;
     RECT  2.16 34.965 49.68 35.235 ;
     RECT  2.16 35.505 49.68 35.775 ;
     RECT  2.16 36.045 49.68 36.315 ;
     RECT  2.16 36.585 49.68 36.855 ;
     RECT  2.16 37.125 49.68 37.395 ;
     RECT  2.16 37.665 49.68 37.935 ;
     RECT  2.16 38.205 49.68 38.475 ;
     RECT  2.16 38.745 49.68 39.015 ;
     RECT  2.16 39.285 49.68 39.555 ;
     RECT  2.16 39.825 49.68 40.095 ;
     RECT  2.16 40.365 49.68 40.635 ;
     RECT  2.16 40.905 49.68 41.175 ;
     RECT  2.16 41.445 49.68 41.715 ;
     RECT  2.16 41.985 49.68 42.255 ;
     RECT  2.16 42.525 49.68 42.795 ;
     RECT  2.16 43.065 49.68 43.335 ;
     RECT  2.16 43.605 49.68 43.875 ;
     RECT  2.16 44.145 49.68 44.415 ;
     RECT  2.16 44.685 49.68 44.955 ;
     RECT  2.16 45.225 49.68 45.495 ;
     RECT  2.16 45.765 49.68 46.035 ;
     RECT  2.16 46.305 49.68 46.575 ;
     RECT  2.16 46.845 49.68 47.115 ;
     RECT  2.16 47.385 49.68 47.655 ;
     RECT  2.16 47.925 49.68 48.195 ;
     RECT  2.16 48.465 49.68 48.735 ;
     RECT  2.16 49.005 49.68 49.275 ;
     RECT  2.16 49.545 49.68 49.68 ;
    LAYER RVTP ;
     RECT  2.16 2.295 49.68 2.565 ;
     RECT  2.16 2.835 49.68 3.105 ;
     RECT  2.16 3.375 49.68 3.645 ;
     RECT  2.16 3.915 49.68 4.185 ;
     RECT  2.16 4.455 49.68 4.725 ;
     RECT  2.16 4.995 49.68 5.265 ;
     RECT  2.16 5.535 49.68 5.805 ;
     RECT  2.16 6.075 49.68 6.345 ;
     RECT  2.16 6.615 49.68 6.885 ;
     RECT  2.16 7.155 49.68 7.425 ;
     RECT  2.16 7.695 49.68 7.965 ;
     RECT  2.16 8.235 49.68 8.505 ;
     RECT  2.16 8.775 49.68 9.045 ;
     RECT  2.16 9.315 49.68 9.585 ;
     RECT  2.16 9.855 49.68 10.125 ;
     RECT  2.16 10.395 49.68 10.665 ;
     RECT  2.16 10.935 49.68 11.205 ;
     RECT  2.16 11.475 49.68 11.745 ;
     RECT  2.16 12.015 49.68 12.285 ;
     RECT  2.16 12.555 49.68 12.825 ;
     RECT  2.16 13.095 49.68 13.365 ;
     RECT  2.16 13.635 49.68 13.905 ;
     RECT  2.16 14.175 49.68 14.445 ;
     RECT  2.16 14.715 49.68 14.985 ;
     RECT  2.16 15.255 49.68 15.525 ;
     RECT  2.16 15.795 49.68 16.065 ;
     RECT  2.16 16.335 49.68 16.605 ;
     RECT  2.16 16.875 49.68 17.145 ;
     RECT  2.16 17.415 49.68 17.685 ;
     RECT  2.16 17.955 49.68 18.225 ;
     RECT  2.16 18.495 49.68 18.765 ;
     RECT  2.16 19.035 49.68 19.305 ;
     RECT  2.16 19.575 49.68 19.845 ;
     RECT  2.16 20.115 49.68 20.385 ;
     RECT  2.16 20.655 49.68 20.925 ;
     RECT  2.16 21.195 49.68 21.465 ;
     RECT  2.16 21.735 49.68 22.005 ;
     RECT  2.16 22.275 49.68 22.545 ;
     RECT  2.16 22.815 49.68 23.085 ;
     RECT  2.16 23.355 49.68 23.625 ;
     RECT  2.16 23.895 49.68 24.165 ;
     RECT  2.16 24.435 49.68 24.705 ;
     RECT  2.16 24.975 49.68 25.245 ;
     RECT  2.16 25.515 49.68 25.785 ;
     RECT  2.16 26.055 49.68 26.325 ;
     RECT  2.16 26.595 49.68 26.865 ;
     RECT  2.16 27.135 49.68 27.405 ;
     RECT  2.16 27.675 49.68 27.945 ;
     RECT  2.16 28.215 49.68 28.485 ;
     RECT  2.16 28.755 49.68 29.025 ;
     RECT  2.16 29.295 49.68 29.565 ;
     RECT  2.16 29.835 49.68 30.105 ;
     RECT  2.16 30.375 49.68 30.645 ;
     RECT  2.16 30.915 49.68 31.185 ;
     RECT  2.16 31.455 49.68 31.725 ;
     RECT  2.16 31.995 49.68 32.265 ;
     RECT  2.16 32.535 49.68 32.805 ;
     RECT  2.16 33.075 49.68 33.345 ;
     RECT  2.16 33.615 49.68 33.885 ;
     RECT  2.16 34.155 49.68 34.425 ;
     RECT  2.16 34.695 49.68 34.965 ;
     RECT  2.16 35.235 49.68 35.505 ;
     RECT  2.16 35.775 49.68 36.045 ;
     RECT  2.16 36.315 49.68 36.585 ;
     RECT  2.16 36.855 49.68 37.125 ;
     RECT  2.16 37.395 49.68 37.665 ;
     RECT  2.16 37.935 49.68 38.205 ;
     RECT  2.16 38.475 49.68 38.745 ;
     RECT  2.16 39.015 49.68 39.285 ;
     RECT  2.16 39.555 49.68 39.825 ;
     RECT  2.16 40.095 49.68 40.365 ;
     RECT  2.16 40.635 49.68 40.905 ;
     RECT  2.16 41.175 49.68 41.445 ;
     RECT  2.16 41.715 49.68 41.985 ;
     RECT  2.16 42.255 49.68 42.525 ;
     RECT  2.16 42.795 49.68 43.065 ;
     RECT  2.16 43.335 49.68 43.605 ;
     RECT  2.16 43.875 49.68 44.145 ;
     RECT  2.16 44.415 49.68 44.685 ;
     RECT  2.16 44.955 49.68 45.225 ;
     RECT  2.16 45.495 49.68 45.765 ;
     RECT  2.16 46.035 49.68 46.305 ;
     RECT  2.16 46.575 49.68 46.845 ;
     RECT  2.16 47.115 49.68 47.385 ;
     RECT  2.16 47.655 49.68 47.925 ;
     RECT  2.16 48.195 49.68 48.465 ;
     RECT  2.16 48.735 49.68 49.005 ;
     RECT  2.16 49.275 49.68 49.545 ;
    LAYER M1 ;
     RECT  2.16 2.151 49.68 49.689 ;
    LAYER M2 ;
     RECT  0.103 22.212 2.16 22.23 ;
     RECT  0.535 27.342 2.16 27.36 ;
     RECT  0.103 32.472 2.16 32.49 ;
     RECT  2.16 2.151 49.68 49.689 ;
     RECT  49.68 27.846 49.883 28.404 ;
     RECT  49.883 27.846 50.675 28.134 ;
     RECT  49.68 23.904 50.711 25.344 ;
     RECT  49.68 26.226 50.711 26.514 ;
     RECT  50.675 28.116 50.711 28.134 ;
     RECT  50.711 23.904 50.747 24.498 ;
     RECT  50.711 25.326 50.747 25.344 ;
    LAYER M3 ;
     RECT  22.248 0.571 22.266 1.723 ;
     RECT  23.94 0.571 23.958 1.723 ;
     RECT  25.668 0.571 25.686 1.723 ;
     RECT  18.972 1.723 32.598 2.143 ;
     RECT  18.615 2.143 32.598 2.371 ;
     RECT  2.415 2.143 2.505 2.413 ;
     RECT  7.815 2.143 7.905 2.413 ;
     RECT  13.215 2.143 13.305 2.413 ;
     RECT  34.815 2.143 34.905 2.413 ;
     RECT  40.215 2.143 40.305 2.413 ;
     RECT  45.615 2.143 45.705 2.413 ;
     RECT  18.615 2.371 33.102 3.379 ;
     RECT  18.615 3.379 33.246 3.569 ;
     RECT  19.764 3.569 33.246 3.947 ;
     RECT  20.16 3.947 33.246 3.955 ;
     RECT  20.16 3.955 33.57 3.965 ;
     RECT  20.628 3.965 33.57 4.109 ;
     RECT  20.736 4.109 33.57 4.181 ;
     RECT  20.916 4.181 33.57 4.261 ;
     RECT  20.916 4.261 34.002 4.289 ;
     RECT  20.988 4.289 34.002 4.415 ;
     RECT  2.415 2.413 2.697 8.977 ;
     RECT  4.608 8.941 4.626 8.977 ;
     RECT  2.415 8.977 3.294 9.013 ;
     RECT  4.068 8.977 4.626 9.013 ;
     RECT  2.415 9.013 4.626 9.247 ;
     RECT  2.34 9.247 4.626 9.275 ;
     RECT  4.608 9.275 4.626 9.349 ;
     RECT  5.796 9.319 5.814 9.355 ;
     RECT  5.616 9.355 5.814 9.391 ;
     RECT  34.815 2.413 35.097 9.481 ;
     RECT  5.616 9.391 6.534 9.509 ;
     RECT  34.776 9.481 35.097 9.533 ;
     RECT  36.576 9.643 36.594 9.689 ;
     RECT  2.34 9.275 3.834 9.691 ;
     RECT  34.815 9.533 35.097 9.787 ;
     RECT  5.688 9.509 6.534 9.931 ;
     RECT  34.815 9.787 35.19 9.965 ;
     RECT  5.688 9.931 6.786 10.093 ;
     RECT  7.815 2.413 8.097 10.201 ;
     RECT  4.608 9.349 4.842 10.267 ;
     RECT  5.688 10.093 6.822 10.319 ;
     RECT  7.704 10.201 8.097 10.471 ;
     RECT  2.304 9.691 3.834 10.597 ;
     RECT  4.572 10.267 4.842 10.597 ;
     RECT  7.704 10.471 8.226 10.633 ;
     RECT  6.588 10.319 6.822 10.669 ;
     RECT  7.704 10.633 8.406 10.669 ;
     RECT  6.588 10.669 8.406 10.741 ;
     RECT  6.588 10.741 8.946 10.829 ;
     RECT  2.304 10.597 4.842 11.129 ;
     RECT  5.796 10.319 5.814 11.137 ;
     RECT  3.816 11.129 4.842 11.173 ;
     RECT  5.58 11.137 5.814 11.173 ;
     RECT  3.816 11.173 5.814 11.281 ;
     RECT  6.588 10.829 8.097 11.281 ;
     RECT  2.304 11.129 2.826 11.453 ;
     RECT  3.816 11.281 8.097 11.749 ;
     RECT  8.928 10.829 8.946 11.749 ;
     RECT  3.816 11.749 8.946 11.939 ;
     RECT  8.892 11.939 8.946 11.947 ;
     RECT  3.816 11.939 8.097 11.975 ;
     RECT  3.816 11.975 6.606 11.981 ;
     RECT  8.892 11.947 9.45 12.209 ;
     RECT  2.304 11.453 2.697 12.595 ;
     RECT  3.816 11.981 4.626 12.595 ;
     RECT  2.304 12.595 4.626 12.757 ;
     RECT  5.724 11.981 6.606 12.757 ;
     RECT  2.304 12.757 4.842 12.797 ;
     RECT  5.652 12.757 6.606 13.055 ;
     RECT  5.724 13.055 6.606 13.297 ;
     RECT  7.416 11.975 8.097 13.297 ;
     RECT  5.724 13.297 8.097 13.595 ;
     RECT  7.416 13.595 8.097 13.711 ;
     RECT  8.928 12.209 9.45 13.711 ;
     RECT  2.304 12.797 4.626 14.369 ;
     RECT  2.304 14.369 3.15 14.405 ;
     RECT  5.724 13.595 6.606 14.755 ;
     RECT  3.96 14.369 4.626 14.779 ;
     RECT  3.96 14.779 4.878 14.819 ;
     RECT  5.616 14.755 6.606 14.909 ;
     RECT  5.796 14.909 6.606 14.917 ;
     RECT  7.416 13.711 9.45 14.917 ;
     RECT  3.96 14.819 4.626 15.421 ;
     RECT  2.304 14.405 2.697 15.835 ;
     RECT  3.816 15.421 4.626 15.835 ;
     RECT  2.304 15.835 4.626 15.931 ;
     RECT  2.304 15.931 4.878 16.025 ;
     RECT  2.304 16.025 2.697 16.295 ;
     RECT  5.796 14.917 9.45 16.375 ;
     RECT  3.816 16.025 4.878 16.411 ;
     RECT  5.616 16.375 9.45 16.411 ;
     RECT  3.816 16.411 9.45 16.529 ;
     RECT  20.268 16.267 20.286 16.709 ;
     RECT  21.06 16.681 21.078 16.795 ;
     RECT  20.52 16.795 21.078 16.835 ;
     RECT  21.06 16.835 21.078 17.021 ;
     RECT  2.415 16.295 2.697 17.035 ;
     RECT  2.412 17.035 2.697 17.105 ;
     RECT  5.724 16.529 9.45 17.141 ;
     RECT  3.816 16.529 4.626 17.581 ;
     RECT  2.415 17.105 2.697 17.611 ;
     RECT  3.816 17.581 4.878 17.611 ;
     RECT  5.724 17.141 6.606 17.617 ;
     RECT  2.415 17.611 4.878 17.761 ;
     RECT  5.652 17.617 6.606 17.761 ;
     RECT  2.415 17.761 6.606 18.331 ;
     RECT  2.304 18.331 6.606 18.455 ;
     RECT  2.415 18.455 6.606 18.535 ;
     RECT  7.416 17.141 9.45 18.535 ;
     RECT  21.888 4.415 34.002 19.031 ;
     RECT  2.415 18.535 9.45 19.195 ;
     RECT  2.304 19.195 9.45 19.265 ;
     RECT  21.888 19.031 33.786 19.337 ;
     RECT  2.415 19.265 9.45 19.535 ;
     RECT  2.415 19.535 2.79 19.805 ;
     RECT  30.492 19.337 33.786 19.805 ;
     RECT  30.492 19.805 33.57 19.949 ;
     RECT  2.415 19.805 2.697 20.047 ;
     RECT  3.852 19.535 9.45 20.075 ;
     RECT  3.852 20.075 4.914 20.731 ;
     RECT  21.888 19.337 29.697 20.857 ;
     RECT  30.492 19.949 33.03 20.857 ;
     RECT  2.304 20.047 2.697 21.067 ;
     RECT  3.744 20.731 4.914 21.067 ;
     RECT  21.888 20.857 33.03 21.271 ;
     RECT  2.304 21.067 4.914 21.397 ;
     RECT  5.724 20.075 9.45 21.397 ;
     RECT  2.304 21.397 9.45 21.425 ;
     RECT  21.888 21.271 33.102 21.433 ;
     RECT  3.672 21.425 9.45 21.461 ;
     RECT  21.888 21.433 33.246 21.541 ;
     RECT  21.888 21.541 33.354 21.631 ;
     RECT  3.672 21.461 3.978 21.695 ;
     RECT  4.788 21.461 9.45 21.695 ;
     RECT  5.724 21.695 9.45 21.703 ;
     RECT  5.724 21.703 9.594 21.775 ;
     RECT  2.415 21.425 2.79 21.965 ;
     RECT  5.724 21.775 9.666 22.001 ;
     RECT  21.888 21.631 33.498 22.081 ;
     RECT  3.672 21.695 3.87 22.171 ;
     RECT  5.724 22.001 9.594 22.199 ;
     RECT  5.724 22.199 9.45 22.235 ;
     RECT  0.108 22.207 0.126 22.253 ;
     RECT  34.815 9.965 35.097 22.351 ;
     RECT  21.888 22.081 33.642 22.469 ;
     RECT  22.14 22.469 33.642 22.477 ;
     RECT  34.815 22.351 35.73 22.477 ;
     RECT  5.724 22.235 9.414 22.505 ;
     RECT  8.928 22.505 9.414 22.589 ;
     RECT  2.415 21.965 2.697 22.651 ;
     RECT  4.788 21.695 4.914 22.711 ;
     RECT  22.14 22.477 35.73 22.775 ;
     RECT  40.215 2.413 40.497 22.783 ;
     RECT  2.304 22.651 2.697 22.795 ;
     RECT  3.42 22.171 3.87 22.795 ;
     RECT  2.304 22.795 3.87 22.855 ;
     RECT  4.608 22.711 4.914 22.855 ;
     RECT  22.14 22.775 35.478 23.081 ;
     RECT  2.304 22.855 4.914 23.395 ;
     RECT  5.724 22.505 8.154 23.395 ;
     RECT  34.815 23.081 35.478 23.701 ;
     RECT  22.14 23.081 34.074 23.971 ;
     RECT  34.815 23.701 35.586 23.971 ;
     RECT  47.484 23.899 47.502 23.971 ;
     RECT  48.42 23.791 48.438 23.971 ;
     RECT  2.304 23.395 8.154 24.043 ;
     RECT  2.304 24.043 8.19 24.061 ;
     RECT  22.14 23.971 35.586 24.089 ;
     RECT  47.484 23.971 48.438 24.089 ;
     RECT  49.356 23.935 49.374 24.089 ;
     RECT  2.304 24.061 8.262 24.091 ;
     RECT  9.252 22.589 9.414 24.091 ;
     RECT  45.615 2.413 45.897 24.097 ;
     RECT  46.728 23.665 46.746 24.097 ;
     RECT  45.615 24.097 46.746 24.133 ;
     RECT  47.484 24.089 48.366 24.133 ;
     RECT  34.668 24.089 35.586 24.241 ;
     RECT  34.668 24.241 35.73 24.395 ;
     RECT  45.615 24.133 48.366 24.475 ;
     RECT  22.14 24.089 33.894 24.526 ;
     RECT  50.724 23.899 50.742 24.571 ;
     RECT  2.304 24.091 9.414 24.629 ;
     RECT  34.668 24.395 35.298 24.629 ;
     RECT  50.688 24.571 50.742 24.629 ;
     RECT  2.304 24.629 3.15 24.665 ;
     RECT  22.14 24.526 33.606 24.665 ;
     RECT  45.54 24.475 48.366 24.899 ;
     RECT  45.54 24.899 46.746 25.051 ;
     RECT  3.888 24.629 9.414 25.169 ;
     RECT  44.856 25.051 46.746 25.169 ;
     RECT  44.856 25.169 46.242 25.177 ;
     RECT  43.128 25.177 43.146 25.213 ;
     RECT  43.956 25.051 43.974 25.213 ;
     RECT  44.748 25.177 46.242 25.213 ;
     RECT  42.912 25.213 43.146 25.249 ;
     RECT  34.776 24.629 35.298 25.321 ;
     RECT  42.3 25.249 43.146 25.321 ;
     RECT  43.956 25.213 46.242 25.321 ;
     RECT  40.215 22.783 41.022 25.349 ;
     RECT  50.724 24.629 50.742 25.435 ;
     RECT  3.888 25.169 4.914 25.475 ;
     RECT  42.3 25.321 46.242 25.475 ;
     RECT  42.3 25.475 44.514 25.517 ;
     RECT  22.14 24.665 33.318 25.519 ;
     RECT  42.732 25.517 44.514 25.547 ;
     RECT  42.732 25.547 43.974 25.583 ;
     RECT  22.14 25.519 33.354 25.591 ;
     RECT  34.776 25.321 35.982 25.591 ;
     RECT  47.664 24.899 48.366 25.591 ;
     RECT  34.776 25.591 36.27 25.709 ;
     RECT  22.14 25.591 33.642 25.717 ;
     RECT  34.776 25.709 35.097 25.717 ;
     RECT  2.304 24.665 2.697 25.745 ;
     RECT  47.664 25.591 48.474 25.861 ;
     RECT  49.248 24.475 49.266 25.861 ;
     RECT  50.688 25.435 50.742 25.901 ;
     RECT  47.664 25.861 49.266 25.951 ;
     RECT  37.008 24.475 37.026 25.979 ;
     RECT  21.348 23.971 21.366 26.011 ;
     RECT  22.14 25.717 35.097 26.011 ;
     RECT  45.504 25.475 46.242 26.095 ;
     RECT  3.564 25.861 3.582 26.131 ;
     RECT  35.928 25.709 36.27 26.131 ;
     RECT  45.504 26.095 46.35 26.131 ;
     RECT  47.34 25.951 49.266 26.131 ;
     RECT  21.348 26.011 35.097 26.237 ;
     RECT  45.504 26.131 49.302 26.249 ;
     RECT  2.415 25.745 2.697 26.257 ;
     RECT  3.42 26.131 3.582 26.257 ;
     RECT  4.428 25.475 4.914 26.257 ;
     RECT  45.504 26.249 47.358 26.333 ;
     RECT  48.528 26.249 49.302 26.491 ;
     RECT  48.528 26.491 49.338 26.519 ;
     RECT  50.688 25.901 50.706 26.519 ;
     RECT  45.615 26.333 47.358 26.555 ;
     RECT  49.068 26.519 49.338 26.591 ;
     RECT  5.724 25.169 9.414 26.635 ;
     RECT  5.688 26.635 9.414 26.671 ;
     RECT  40.215 25.349 40.497 26.671 ;
     RECT  42.732 25.583 42.93 26.671 ;
     RECT  43.956 25.583 43.974 26.671 ;
     RECT  42.732 26.671 44.118 26.731 ;
     RECT  2.415 26.257 4.914 26.761 ;
     RECT  5.688 26.671 9.666 26.761 ;
     RECT  39.888 26.671 40.497 26.779 ;
     RECT  2.415 26.761 9.666 26.789 ;
     RECT  42.372 26.731 44.118 26.789 ;
     RECT  22.14 26.237 35.097 26.797 ;
     RECT  35.928 26.131 36.45 26.797 ;
     RECT  22.14 26.797 36.45 26.905 ;
     RECT  2.415 26.789 9.594 26.971 ;
     RECT  44.496 26.797 44.694 27.059 ;
     RECT  45.615 26.555 46.53 27.067 ;
     RECT  2.304 26.971 9.594 27.095 ;
     RECT  39.888 26.779 40.59 27.095 ;
     RECT  44.676 27.059 44.694 27.095 ;
     RECT  47.304 26.555 47.358 27.211 ;
     RECT  45.612 27.067 46.53 27.301 ;
     RECT  47.304 27.211 47.898 27.301 ;
     RECT  22.14 26.905 36.486 27.329 ;
     RECT  42.372 26.789 43.326 27.401 ;
     RECT  0.54 27.337 0.558 27.437 ;
     RECT  45.036 27.301 47.898 27.481 ;
     RECT  49.068 26.591 49.086 27.481 ;
     RECT  50.652 27.163 50.67 27.595 ;
     RECT  42.372 27.401 43.146 27.599 ;
     RECT  35.82 27.329 35.946 27.635 ;
     RECT  42.732 27.599 43.146 27.635 ;
     RECT  45.036 27.481 49.086 27.635 ;
     RECT  2.415 27.095 9.594 27.679 ;
     RECT  22.14 27.329 35.097 27.725 ;
     RECT  45.615 27.635 49.086 27.751 ;
     RECT  49.86 26.731 49.878 27.751 ;
     RECT  2.415 27.679 10.026 27.835 ;
     RECT  2.304 27.835 10.026 27.869 ;
     RECT  40.215 27.095 40.59 27.869 ;
     RECT  50.652 27.595 50.706 27.869 ;
     RECT  2.304 27.869 9.666 27.875 ;
     RECT  23.076 27.725 35.097 27.905 ;
     RECT  45.615 27.751 49.878 27.905 ;
     RECT  35.928 27.635 35.946 27.941 ;
     RECT  47.304 27.905 49.878 27.941 ;
     RECT  2.304 27.875 9.522 28.139 ;
     RECT  38.952 27.877 38.97 28.139 ;
     RECT  50.688 27.869 50.706 28.139 ;
     RECT  2.304 28.139 9.45 28.175 ;
     RECT  47.988 27.941 49.878 28.175 ;
     RECT  49.068 28.175 49.878 28.211 ;
     RECT  2.415 28.175 9.45 28.409 ;
     RECT  49.86 28.211 49.878 28.409 ;
     RECT  49.068 28.211 49.086 28.445 ;
     RECT  41.976 27.715 41.994 28.679 ;
     RECT  23.184 27.905 35.097 28.687 ;
     RECT  2.415 28.409 9.378 28.715 ;
     RECT  23.184 28.687 35.19 28.795 ;
     RECT  23.184 28.795 35.622 28.831 ;
     RECT  3.42 28.715 9.378 28.949 ;
     RECT  3.456 28.949 9.378 29.021 ;
     RECT  23.184 28.831 35.838 29.101 ;
     RECT  2.415 28.715 2.697 29.131 ;
     RECT  38.844 28.795 38.862 29.219 ;
     RECT  23.184 29.101 36.018 29.299 ;
     RECT  3.528 29.021 9.378 29.399 ;
     RECT  23.184 29.299 36.126 29.489 ;
     RECT  23.184 29.489 36.018 29.525 ;
     RECT  23.184 29.525 35.946 29.795 ;
     RECT  2.304 29.131 2.697 29.851 ;
     RECT  3.528 29.399 4.914 29.851 ;
     RECT  30.852 29.795 35.946 29.867 ;
     RECT  31.392 29.867 35.946 29.903 ;
     RECT  31.428 29.903 35.946 30.029 ;
     RECT  2.304 29.851 4.914 30.065 ;
     RECT  2.415 30.065 4.914 30.181 ;
     RECT  5.652 29.399 9.378 30.181 ;
     RECT  31.5 30.029 35.946 30.299 ;
     RECT  2.415 30.181 9.378 30.335 ;
     RECT  23.184 29.795 30.114 30.721 ;
     RECT  23.184 30.721 30.186 30.763 ;
     RECT  5.868 30.335 9.378 30.907 ;
     RECT  5.868 30.907 9.594 30.919 ;
     RECT  5.868 30.919 10.17 30.955 ;
     RECT  5.868 30.955 10.35 30.991 ;
     RECT  5.868 30.991 10.89 31.109 ;
     RECT  31.5 30.299 35.838 31.117 ;
     RECT  23.184 30.763 30.618 31.195 ;
     RECT  31.392 31.117 35.838 31.195 ;
     RECT  10.332 31.109 10.89 31.217 ;
     RECT  23.184 31.195 35.838 31.217 ;
     RECT  21.348 26.237 21.366 31.261 ;
     RECT  25.092 31.217 35.838 31.289 ;
     RECT  2.415 30.335 5.058 31.291 ;
     RECT  42.732 27.635 42.75 31.379 ;
     RECT  2.304 31.291 5.058 31.415 ;
     RECT  10.332 31.217 10.458 31.415 ;
     RECT  2.34 31.415 5.058 31.459 ;
     RECT  5.868 31.109 9.306 31.459 ;
     RECT  42.624 31.531 42.642 31.649 ;
     RECT  2.34 31.459 9.306 31.721 ;
     RECT  2.34 31.721 4.734 31.955 ;
     RECT  5.472 31.721 9.306 31.955 ;
     RECT  2.34 31.955 2.697 32.155 ;
     RECT  2.304 32.155 2.697 32.225 ;
     RECT  25.092 31.289 35.097 32.237 ;
     RECT  27.72 32.237 35.097 32.369 ;
     RECT  6.012 31.955 9.306 32.459 ;
     RECT  0.108 32.467 0.126 32.621 ;
     RECT  3.42 31.955 4.734 32.701 ;
     RECT  27.864 32.369 35.097 32.729 ;
     RECT  2.415 32.225 2.697 32.731 ;
     RECT  3.42 32.701 4.986 32.731 ;
     RECT  2.415 32.731 4.986 32.801 ;
     RECT  27.864 32.729 31.518 32.909 ;
     RECT  2.415 32.801 4.734 33.007 ;
     RECT  6.012 32.459 9.234 33.043 ;
     RECT  25.092 32.237 26.478 33.043 ;
     RECT  2.304 33.007 4.734 33.305 ;
     RECT  3.42 33.305 4.734 33.583 ;
     RECT  5.904 33.043 9.234 33.619 ;
     RECT  5.724 33.619 9.234 33.655 ;
     RECT  3.42 33.583 4.842 33.691 ;
     RECT  5.688 33.655 9.234 33.691 ;
     RECT  3.42 33.691 9.234 33.809 ;
     RECT  3.456 33.809 4.878 33.881 ;
     RECT  2.304 33.305 2.697 33.953 ;
     RECT  3.6 33.881 4.878 34.151 ;
     RECT  2.412 33.953 2.697 34.385 ;
     RECT  5.724 33.809 9.234 34.529 ;
     RECT  5.724 34.529 9.198 34.627 ;
     RECT  3.6 34.151 4.842 34.699 ;
     RECT  2.415 34.385 2.697 34.771 ;
     RECT  3.42 34.699 4.842 34.771 ;
     RECT  2.415 34.771 4.842 35.213 ;
     RECT  3.42 35.213 4.842 35.311 ;
     RECT  5.688 34.627 9.198 35.311 ;
     RECT  20.736 31.261 21.366 35.311 ;
     RECT  20.196 35.311 21.366 35.405 ;
     RECT  3.42 35.311 9.198 35.465 ;
     RECT  4.212 35.465 9.198 35.501 ;
     RECT  2.415 35.213 2.697 35.611 ;
     RECT  4.464 35.501 9.198 35.969 ;
     RECT  4.464 35.969 8.766 36.311 ;
     RECT  25.092 33.043 26.514 36.475 ;
     RECT  25.092 36.475 26.874 36.481 ;
     RECT  2.304 35.611 2.697 36.517 ;
     RECT  4.464 36.311 4.878 36.517 ;
     RECT  2.304 36.517 3.294 36.553 ;
     RECT  4.032 36.517 4.878 36.553 ;
     RECT  5.724 36.311 8.766 37.057 ;
     RECT  2.304 36.553 4.878 37.201 ;
     RECT  5.652 37.057 8.766 37.201 ;
     RECT  25.092 36.481 27.234 37.613 ;
     RECT  2.304 37.201 8.766 38.705 ;
     RECT  2.412 38.705 8.766 38.939 ;
     RECT  5.58 38.939 8.766 38.975 ;
     RECT  2.412 38.939 4.554 39.101 ;
     RECT  10.44 31.415 10.458 39.209 ;
     RECT  2.415 39.101 4.554 39.245 ;
     RECT  2.415 39.245 3.042 39.317 ;
     RECT  5.796 38.975 8.766 39.749 ;
     RECT  2.415 39.317 2.898 39.931 ;
     RECT  5.796 39.749 8.73 40.099 ;
     RECT  2.304 39.931 2.898 40.135 ;
     RECT  3.816 39.245 4.554 40.135 ;
     RECT  2.304 40.135 4.554 40.267 ;
     RECT  2.304 40.267 4.734 40.297 ;
     RECT  5.688 40.099 8.73 40.297 ;
     RECT  2.304 40.297 8.73 40.325 ;
     RECT  2.304 40.325 2.697 40.865 ;
     RECT  3.42 40.325 8.73 41.099 ;
     RECT  3.42 41.099 4.662 41.171 ;
     RECT  2.415 40.865 2.697 41.251 ;
     RECT  3.42 41.171 4.554 41.251 ;
     RECT  5.904 41.099 8.73 41.611 ;
     RECT  2.415 41.251 4.554 41.647 ;
     RECT  5.904 41.611 9.198 41.648 ;
     RECT  5.904 41.648 9.054 41.789 ;
     RECT  2.304 41.647 4.554 42.187 ;
     RECT  2.304 42.187 4.842 42.223 ;
     RECT  2.304 42.223 4.878 42.251 ;
     RECT  5.904 41.789 8.73 42.259 ;
     RECT  5.796 42.259 8.73 42.295 ;
     RECT  3.456 42.251 4.878 42.323 ;
     RECT  5.688 42.295 8.73 42.449 ;
     RECT  2.304 42.251 2.697 42.755 ;
     RECT  6.192 42.449 8.73 42.763 ;
     RECT  22.14 27.725 22.266 42.763 ;
     RECT  6.192 42.763 8.946 42.893 ;
     RECT  3.996 42.323 4.878 42.961 ;
     RECT  6.228 42.893 8.946 42.989 ;
     RECT  20.736 35.405 21.366 42.997 ;
     RECT  2.34 42.755 2.697 43.025 ;
     RECT  3.996 42.961 5.166 43.025 ;
     RECT  4.68 43.025 5.166 43.061 ;
     RECT  14.832 42.997 14.85 43.097 ;
     RECT  6.624 42.989 8.946 43.141 ;
     RECT  13.215 2.413 13.497 43.141 ;
     RECT  4.68 43.061 4.878 43.295 ;
     RECT  13.215 43.141 13.626 43.295 ;
     RECT  4.86 43.295 4.878 43.331 ;
     RECT  6.624 43.141 9.126 43.331 ;
     RECT  7.056 43.331 9.126 43.799 ;
     RECT  7.056 43.799 9.09 43.835 ;
     RECT  18.615 3.569 18.897 43.843 ;
     RECT  9.072 43.835 9.09 43.871 ;
     RECT  7.056 43.835 8.097 44.539 ;
     RECT  6.84 44.539 8.097 44.587 ;
     RECT  6.84 44.587 8.19 44.609 ;
     RECT  7.056 44.609 8.19 44.761 ;
     RECT  7.056 44.761 8.226 44.879 ;
     RECT  14.832 44.587 14.85 45.005 ;
     RECT  7.056 44.879 8.097 45.841 ;
     RECT  20.412 42.997 21.366 45.841 ;
     RECT  22.14 42.763 22.338 45.841 ;
     RECT  6.408 45.841 8.097 45.959 ;
     RECT  20.412 45.841 22.338 45.959 ;
     RECT  25.092 37.613 26.514 46.067 ;
     RECT  7.02 45.959 8.097 46.109 ;
     RECT  20.484 45.959 22.338 46.345 ;
     RECT  23.184 31.217 24.297 46.345 ;
     RECT  32.292 32.729 35.097 46.651 ;
     RECT  35.82 31.289 35.838 46.651 ;
     RECT  10.404 39.289 10.422 46.747 ;
     RECT  6.228 46.075 6.246 46.777 ;
     RECT  7.02 46.109 7.074 46.777 ;
     RECT  9.396 46.747 9.414 46.777 ;
     RECT  10.152 46.747 10.422 46.777 ;
     RECT  14.904 46.741 14.922 46.777 ;
     RECT  20.484 46.345 24.297 46.777 ;
     RECT  9.216 46.777 10.422 46.813 ;
     RECT  14.868 46.777 14.922 46.841 ;
     RECT  9.216 46.813 10.53 46.885 ;
     RECT  31.5 32.909 31.518 46.885 ;
     RECT  32.292 46.651 35.838 46.885 ;
     RECT  6.228 46.777 7.074 46.921 ;
     RECT  16.884 46.843 16.902 47.011 ;
     RECT  18.615 43.843 19.206 47.011 ;
     RECT  6.192 46.921 7.074 47.039 ;
     RECT  14.868 46.841 14.886 47.039 ;
     RECT  9.216 46.885 10.854 47.047 ;
     RECT  28.008 32.909 30.402 47.083 ;
     RECT  18.615 47.011 19.242 47.119 ;
     RECT  20.412 46.777 24.297 47.119 ;
     RECT  16.884 47.011 17.622 47.155 ;
     RECT  28.008 47.083 30.726 47.155 ;
     RECT  31.5 46.885 35.838 47.155 ;
     RECT  8.928 47.047 10.854 47.183 ;
     RECT  6.228 47.039 7.074 47.191 ;
     RECT  7.815 46.109 8.097 47.191 ;
     RECT  8.928 47.183 9.414 47.191 ;
     RECT  28.008 47.155 35.838 47.191 ;
     RECT  10.152 47.183 10.854 47.219 ;
     RECT  16.344 47.155 17.622 47.261 ;
     RECT  16.848 47.261 17.622 47.281 ;
     RECT  18.615 47.119 24.297 47.281 ;
     RECT  25.092 46.067 25.974 47.281 ;
     RECT  6.228 47.191 9.414 47.309 ;
     RECT  10.152 47.219 10.17 47.309 ;
     RECT  16.848 47.281 17.766 47.317 ;
     RECT  18.615 47.281 25.974 47.317 ;
     RECT  6.228 47.309 8.154 47.345 ;
     RECT  8.928 47.309 9.09 47.345 ;
     RECT  6.732 47.345 8.154 47.357 ;
     RECT  26.712 47.353 26.73 47.389 ;
     RECT  7.344 47.357 8.097 47.405 ;
     RECT  9.072 47.345 9.09 47.405 ;
     RECT  16.848 47.317 25.974 47.425 ;
     RECT  26.712 47.389 27.198 47.425 ;
     RECT  16.848 47.425 27.198 47.461 ;
     RECT  28.008 47.191 36.09 47.461 ;
     RECT  37.332 47.317 37.35 47.461 ;
     RECT  37.116 47.461 37.35 47.551 ;
     RECT  36.828 47.551 37.35 47.579 ;
     RECT  16.848 47.461 36.09 47.731 ;
     RECT  36.828 47.579 37.134 47.731 ;
     RECT  16.848 47.731 37.134 47.849 ;
     RECT  15.804 47.695 15.93 47.857 ;
     RECT  16.848 47.849 36.846 47.891 ;
     RECT  15.732 47.857 15.93 48.001 ;
     RECT  15.408 48.001 15.93 48.235 ;
     RECT  15.408 48.235 16.11 48.361 ;
     RECT  15.228 48.361 16.11 48.397 ;
     RECT  16.848 47.891 27.018 48.397 ;
     RECT  27.828 47.891 36.846 48.659 ;
     RECT  14.796 48.397 27.018 48.775 ;
     RECT  27.828 48.659 36.774 48.775 ;
     RECT  14.796 48.775 36.774 48.803 ;
     RECT  14.832 48.803 36.774 48.929 ;
     RECT  15.624 48.929 36.774 49.307 ;
     RECT  2.415 43.025 2.697 49.427 ;
     RECT  7.815 47.405 8.097 49.427 ;
     RECT  13.215 43.295 13.497 49.427 ;
     RECT  40.215 27.869 40.497 49.427 ;
     RECT  45.615 27.905 45.897 49.427 ;
     RECT  15.696 49.307 36.774 49.469 ;
     RECT  15.84 49.469 26.334 49.517 ;
     RECT  15.84 49.517 16.146 49.565 ;
     RECT  17.028 49.517 25.218 49.565 ;
     RECT  27.36 49.469 36.342 49.565 ;
     RECT  15.912 49.565 15.93 49.577 ;
     RECT  17.028 49.565 17.046 49.577 ;
     RECT  17.784 49.565 24.822 49.577 ;
     RECT  26.316 49.517 26.334 49.577 ;
     RECT  28.692 49.565 30.654 49.577 ;
     RECT  33.444 49.565 35.19 49.577 ;
     RECT  36.036 49.565 36.342 49.577 ;
     RECT  2.415 49.427 2.505 49.697 ;
     RECT  7.815 49.427 7.905 49.697 ;
     RECT  13.215 49.427 13.305 49.697 ;
     RECT  23.832 49.577 24.105 49.697 ;
     RECT  34.704 49.577 34.905 49.697 ;
     RECT  40.215 49.427 40.305 49.697 ;
     RECT  45.615 49.427 45.705 49.697 ;
     RECT  18.216 49.577 18.774 49.805 ;
     RECT  28.98 49.577 29.61 49.805 ;
     RECT  34.704 49.697 34.722 49.853 ;
     RECT  18.216 49.805 18.234 50.765 ;
     RECT  22.104 49.577 22.122 50.765 ;
     RECT  23.832 49.697 23.85 50.765 ;
     RECT  28.98 49.805 28.998 50.765 ;
     RECT  30.636 49.577 30.654 50.765 ;
     RECT  32.436 49.565 32.454 50.765 ;
     RECT  36.324 49.577 36.342 50.765 ;
    LAYER M4 ;
     RECT  0.06 8.832 2.408 42.984 ;
     RECT  2.408 2.148 2.512 49.692 ;
     RECT  2.512 2.418 2.704 49.422 ;
     RECT  2.704 12.768 2.765 13.608 ;
     RECT  2.704 18.768 2.801 19.656 ;
     RECT  2.704 21.072 2.801 21.816 ;
     RECT  2.704 34.752 2.801 35.208 ;
     RECT  2.704 9.072 2.837 11.448 ;
     RECT  2.704 37.008 2.837 37.368 ;
     RECT  2.801 18.768 3.233 19.368 ;
     RECT  2.837 9.072 3.305 10.584 ;
     RECT  2.704 29.856 3.34 31.368 ;
     RECT  2.704 32.736 3.347 32.76 ;
     RECT  3.34 30.192 3.557 31.368 ;
     RECT  3.305 9.36 3.805 10.584 ;
     RECT  2.704 28.416 4.169 28.44 ;
     RECT  3.557 31.344 4.381 31.368 ;
     RECT  3.557 30.192 4.481 30.312 ;
     RECT  4.273 27.84 4.547 27.912 ;
     RECT  4.481 29.664 4.565 30.312 ;
     RECT  3.805 9.36 4.601 11.208 ;
     RECT  4.547 27.84 4.601 27.864 ;
     RECT  3.233 19.344 4.669 19.368 ;
     RECT  4.381 31.344 4.709 31.56 ;
     RECT  2.704 40.272 4.745 40.296 ;
     RECT  2.704 22.8 4.796 22.824 ;
     RECT  3.949 24 4.796 24.024 ;
     RECT  2.704 41.76 4.796 41.784 ;
     RECT  4.601 11.184 4.813 11.208 ;
     RECT  4.669 19.344 4.813 19.992 ;
     RECT  2.801 21.072 4.813 21.096 ;
     RECT  4.796 41.76 4.837 42.216 ;
     RECT  2.704 15.936 4.844 15.96 ;
     RECT  3.949 26.784 4.849 26.808 ;
     RECT  2.704 38.64 4.849 38.664 ;
     RECT  4.837 40.992 4.849 42.216 ;
     RECT  4.601 9.36 4.853 9.672 ;
     RECT  4.813 19.344 4.853 21.432 ;
     RECT  4.565 30.192 4.853 30.312 ;
     RECT  4.796 22.8 4.883 24.936 ;
     RECT  2.801 34.752 4.883 34.776 ;
     RECT  4.849 40.992 4.883 42.792 ;
     RECT  4.853 21.408 4.885 21.432 ;
     RECT  4.883 22.8 4.885 22.824 ;
     RECT  4.844 15.936 4.889 16.44 ;
     RECT  2.837 37.008 4.889 37.032 ;
     RECT  4.849 38.208 4.889 38.664 ;
     RECT  4.837 14.784 4.924 14.808 ;
     RECT  4.885 21.408 4.931 22.824 ;
     RECT  4.853 30.288 4.997 30.312 ;
     RECT  4.813 11.184 5.077 11.256 ;
     RECT  2.765 12.768 5.077 12.792 ;
     RECT  2.704 17.616 5.077 17.64 ;
     RECT  5.077 11.184 5.123 12.792 ;
     RECT  5.077 17.616 5.123 18.264 ;
     RECT  4.853 19.344 5.123 20.184 ;
     RECT  4.883 40.992 5.249 41.016 ;
     RECT  4.883 23.952 5.357 24.024 ;
     RECT  4.889 16.416 5.365 16.44 ;
     RECT  5.123 19.968 5.411 20.184 ;
     RECT  4.889 38.208 5.821 38.232 ;
     RECT  5.123 11.184 5.825 11.976 ;
     RECT  4.849 26.736 5.852 26.808 ;
     RECT  5.533 27.888 5.852 27.912 ;
     RECT  5.852 25.2 5.893 25.224 ;
     RECT  5.852 26.736 5.893 27.912 ;
     RECT  4.853 9.648 5.897 9.672 ;
     RECT  4.709 31.536 5.929 31.56 ;
     RECT  5.893 25.2 5.939 27.912 ;
     RECT  5.929 31.344 5.941 31.56 ;
     RECT  4.799 33.648 6.073 33.672 ;
     RECT  6.073 33.024 6.113 33.672 ;
     RECT  5.821 38.016 6.14 38.232 ;
     RECT  4.883 42.768 6.181 42.792 ;
     RECT  6.181 42.768 6.221 42.888 ;
     RECT  6.14 38.016 6.227 38.376 ;
     RECT  6.277 13.296 6.365 13.848 ;
     RECT  6.289 30.048 6.428 30.072 ;
     RECT  5.941 31.344 6.428 31.896 ;
     RECT  6.113 33.024 6.428 33.048 ;
     RECT  5.411 20.16 6.437 20.184 ;
     RECT  4.931 21.936 6.437 21.96 ;
     RECT  5.365 16.416 6.469 16.536 ;
     RECT  5.123 18.24 6.473 18.264 ;
     RECT  5.357 23.952 6.509 23.976 ;
     RECT  6.428 30.048 6.515 33.048 ;
     RECT  5.939 27.888 6.721 27.912 ;
     RECT  6.515 30.048 6.725 30.072 ;
     RECT  6.721 27.888 6.805 28.536 ;
     RECT  6.227 38.016 6.868 38.04 ;
     RECT  6.721 47.328 6.973 47.352 ;
     RECT  6.973 46.8 7.148 47.352 ;
     RECT  6.829 40.944 7.153 40.968 ;
     RECT  6.221 42.864 7.189 42.888 ;
     RECT  6.181 44.544 7.189 44.568 ;
     RECT  7.148 46.08 7.189 47.352 ;
     RECT  6.433 15.36 7.297 15.384 ;
     RECT  6.469 16.416 7.297 17.112 ;
     RECT  7.189 42.864 7.369 44.568 ;
     RECT  6.397 39.744 7.381 39.768 ;
     RECT  5.825 11.424 7.388 11.976 ;
     RECT  5.939 26.112 7.405 26.52 ;
     RECT  7.388 10.704 7.429 11.976 ;
     RECT  7.297 15.36 7.436 17.112 ;
     RECT  6.865 23.328 7.477 23.352 ;
     RECT  7.436 15.36 7.573 17.544 ;
     RECT  7.405 26.016 7.573 26.52 ;
     RECT  6.805 27.888 7.573 27.912 ;
     RECT  7.58 30.672 7.621 30.696 ;
     RECT  6.868 37.968 7.628 38.04 ;
     RECT  7.621 34.464 7.669 34.488 ;
     RECT  6.469 35.856 7.669 35.88 ;
     RECT  7.153 40.944 7.765 41.064 ;
     RECT  7.429 10.704 7.808 12.024 ;
     RECT  6.365 13.824 7.808 13.848 ;
     RECT  7.573 15.216 7.808 17.544 ;
     RECT  7.477 18.672 7.808 18.84 ;
     RECT  7.477 22.8 7.808 23.352 ;
     RECT  7.573 26.016 7.808 27.912 ;
     RECT  7.621 30.672 7.808 30.792 ;
     RECT  6.515 33.024 7.808 33.048 ;
     RECT  7.669 34.368 7.808 34.488 ;
     RECT  7.669 35.856 7.808 35.976 ;
     RECT  7.628 37.968 7.808 38.376 ;
     RECT  7.381 39.744 7.808 39.816 ;
     RECT  7.765 40.944 7.808 41.4 ;
     RECT  7.369 42.864 7.808 44.712 ;
     RECT  7.189 46.08 7.808 47.4 ;
     RECT  7.808 2.148 7.912 49.692 ;
     RECT  7.912 2.418 8.104 49.422 ;
     RECT  8.104 22.464 8.243 25.032 ;
     RECT  8.104 29.328 8.243 29.544 ;
     RECT  8.104 44.592 8.243 44.808 ;
     RECT  8.243 24.048 8.245 25.032 ;
     RECT  8.104 20.688 8.281 21.096 ;
     RECT  8.104 42.768 8.281 43.608 ;
     RECT  8.281 43.584 8.489 43.608 ;
     RECT  8.104 26.016 8.531 27.912 ;
     RECT  8.104 34.368 8.531 34.488 ;
     RECT  8.104 37.92 8.531 37.944 ;
     RECT  8.104 39.792 8.531 39.816 ;
     RECT  8.104 41.376 8.531 41.784 ;
     RECT  8.104 35.856 8.597 36.024 ;
     RECT  8.531 34.368 8.669 34.392 ;
     RECT  8.597 35.856 8.675 35.88 ;
     RECT  8.281 20.688 8.963 20.712 ;
     RECT  8.243 22.56 8.963 22.584 ;
     RECT  8.245 24.096 8.963 25.032 ;
     RECT  8.531 26.016 8.963 27.864 ;
     RECT  8.104 46.752 9.101 47.4 ;
     RECT  8.104 10.8 9.107 10.824 ;
     RECT  8.104 12 9.107 12.024 ;
     RECT  8.104 13.872 9.107 13.896 ;
     RECT  8.104 15.504 9.107 16.296 ;
     RECT  8.104 17.424 9.107 17.448 ;
     RECT  8.104 19.056 9.107 19.08 ;
     RECT  8.243 29.328 9.107 29.352 ;
     RECT  8.104 32.496 9.107 32.52 ;
     RECT  8.531 41.616 9.107 41.784 ;
     RECT  8.963 26.88 9.209 27.864 ;
     RECT  9.107 41.616 9.209 41.64 ;
     RECT  8.104 30.912 9.241 30.984 ;
     RECT  9.241 30.768 9.353 30.984 ;
     RECT  9.353 30.912 9.605 30.984 ;
     RECT  9.209 27.84 9.677 27.864 ;
     RECT  9.605 30.96 10.181 30.984 ;
     RECT  9.101 46.752 10.181 47.304 ;
     RECT  10.181 46.752 10.643 46.872 ;
     RECT  9.107 16.272 13.208 16.296 ;
     RECT  8.963 25.008 13.208 25.032 ;
     RECT  8.243 44.592 13.208 44.616 ;
     RECT  10.643 46.848 13.208 46.872 ;
     RECT  13.208 2.148 13.312 49.692 ;
     RECT  13.312 2.418 13.504 49.422 ;
     RECT  13.504 44.592 14.821 44.616 ;
     RECT  14.821 44.592 14.861 45 ;
     RECT  13.504 46.848 16.333 46.872 ;
     RECT  16.333 46.848 16.46 47.208 ;
     RECT  15.217 48.384 16.469 48.408 ;
     RECT  16.46 46.848 16.547 47.256 ;
     RECT  16.469 48.384 16.553 48.504 ;
     RECT  15.733 49.536 16.597 49.56 ;
     RECT  16.597 49.488 16.805 49.56 ;
     RECT  16.547 46.848 16.913 47.208 ;
     RECT  16.913 47.04 17.165 47.208 ;
     RECT  16.553 48.384 17.485 48.408 ;
     RECT  18.205 50.736 18.371 50.76 ;
     RECT  17.165 47.04 18.601 47.064 ;
     RECT  17.485 48.336 18.601 48.408 ;
     RECT  13.504 16.272 18.608 16.296 ;
     RECT  13.504 25.008 18.608 25.032 ;
     RECT  15.301 26.016 18.608 26.04 ;
     RECT  14.861 44.976 18.608 45 ;
     RECT  18.601 47.04 18.608 48.408 ;
     RECT  16.805 49.536 18.608 49.56 ;
     RECT  18.608 2.148 18.716 49.692 ;
     RECT  18.716 2.148 18.803 49.8 ;
     RECT  18.803 2.148 18.904 49.56 ;
     RECT  18.904 47.04 19.043 48.504 ;
     RECT  19.043 47.04 19.361 47.256 ;
     RECT  19.043 48.384 19.477 48.504 ;
     RECT  18.904 26.016 20.149 26.04 ;
     RECT  20.141 35.376 20.225 35.4 ;
     RECT  18.904 16.272 20.293 16.296 ;
     RECT  20.293 16.272 20.297 16.824 ;
     RECT  19.361 47.04 20.401 47.208 ;
     RECT  20.401 47.04 20.545 47.4 ;
     RECT  20.297 16.8 20.549 16.824 ;
     RECT  20.149 3.936 20.657 3.96 ;
     RECT  20.545 46.128 20.985 47.4 ;
     RECT  19.477 48.384 20.985 48.408 ;
     RECT  20.985 46.128 21.059 48.408 ;
     RECT  21.059 46.752 21.521 48.408 ;
     RECT  21.229 35.328 21.683 35.352 ;
     RECT  20.149 26.016 21.701 26.232 ;
     RECT  21.625 3.552 21.737 3.576 ;
     RECT  18.904 49.536 21.877 49.56 ;
     RECT  21.836 3.168 21.923 3.192 ;
     RECT  21.049 16.992 21.923 17.016 ;
     RECT  21.877 49.008 21.961 49.56 ;
     RECT  21.701 26.208 22.025 26.232 ;
     RECT  18.904 25.008 22.117 25.032 ;
     RECT  21.521 46.752 22.177 47.928 ;
     RECT  21.961 49.2 22.252 49.56 ;
     RECT  22.093 50.736 22.259 50.76 ;
     RECT  22.193 0.576 22.277 0.6 ;
     RECT  22.177 46.752 22.313 47.88 ;
     RECT  22.313 46.896 22.349 47.88 ;
     RECT  22.349 46.896 22.421 47.4 ;
     RECT  22.117 24.48 22.637 25.032 ;
     RECT  22.421 46.896 22.817 46.92 ;
     RECT  22.561 27.696 23.929 27.72 ;
     RECT  23.821 50.736 23.987 50.76 ;
     RECT  23.821 26.352 24.001 26.376 ;
     RECT  18.961 1.728 24.008 1.752 ;
     RECT  22.741 3.408 24.008 3.432 ;
     RECT  21.877 9.12 24.008 9.144 ;
     RECT  22.849 20.976 24.008 21 ;
     RECT  21.877 22.032 24.008 22.056 ;
     RECT  22.777 23.952 24.008 23.976 ;
     RECT  22.637 25.008 24.008 25.032 ;
     RECT  24.001 26.112 24.008 26.376 ;
     RECT  23.929 27.648 24.008 27.72 ;
     RECT  21.637 36.528 24.008 36.552 ;
     RECT  18.904 44.976 24.008 45 ;
     RECT  22.252 49.536 24.008 49.56 ;
     RECT  23.929 0.576 24.013 0.6 ;
     RECT  24.008 1.728 24.112 49.692 ;
     RECT  24.112 1.728 24.304 49.56 ;
     RECT  24.304 21.936 24.46 25.128 ;
     RECT  24.304 3.408 24.509 3.96 ;
     RECT  24.304 26.112 24.509 27.72 ;
     RECT  24.509 3.936 24.545 3.96 ;
     RECT  24.509 26.304 24.617 27.72 ;
     RECT  24.304 30.384 25.085 30.792 ;
     RECT  24.617 26.304 25.121 26.856 ;
     RECT  25.121 26.592 25.157 26.856 ;
     RECT  24.46 24.384 25.187 25.128 ;
     RECT  25.085 30.384 25.193 30.696 ;
     RECT  25.187 24.912 25.229 25.128 ;
     RECT  24.304 49.536 25.283 49.56 ;
     RECT  25.193 30.384 25.297 30.504 ;
     RECT  24.46 21.936 25.301 23.256 ;
     RECT  24.304 47.328 25.549 47.352 ;
     RECT  25.369 48.384 25.549 48.408 ;
     RECT  25.157 26.64 25.697 26.856 ;
     RECT  25.657 0.576 25.741 0.6 ;
     RECT  25.297 30.288 25.769 30.504 ;
     RECT  25.301 21.936 25.873 22.056 ;
     RECT  25.801 3.936 25.909 3.96 ;
     RECT  25.549 47.328 26.101 48.408 ;
     RECT  25.669 49.488 26.101 49.512 ;
     RECT  25.697 26.64 26.165 26.76 ;
     RECT  25.873 29.088 26.165 29.112 ;
     RECT  26.165 26.64 26.237 26.664 ;
     RECT  26.101 47.328 26.305 49.512 ;
     RECT  25.909 3.936 26.341 4.056 ;
     RECT  25.873 21.696 26.341 22.056 ;
     RECT  25.301 23.088 26.341 23.256 ;
     RECT  26.341 21.168 26.581 23.256 ;
     RECT  26.305 47.328 26.669 49.56 ;
     RECT  26.581 20.88 26.701 23.256 ;
     RECT  25.229 24.912 26.701 24.936 ;
     RECT  24.304 36.528 26.812 36.552 ;
     RECT  26.341 3.888 26.813 4.056 ;
     RECT  26.701 20.88 26.813 24.936 ;
     RECT  26.669 47.328 26.963 47.88 ;
     RECT  26.669 49.008 27.011 49.56 ;
     RECT  25.769 30.288 27.133 30.312 ;
     RECT  26.813 22.032 27.137 24.936 ;
     RECT  26.813 3.936 27.164 4.056 ;
     RECT  25.765 32.208 27.205 32.232 ;
     RECT  27.133 30.288 27.209 31.176 ;
     RECT  26.917 37.584 27.245 37.608 ;
     RECT  27.164 3.936 27.251 4.872 ;
     RECT  27.209 31.152 27.251 31.176 ;
     RECT  27.205 32.208 27.251 32.76 ;
     RECT  26.812 36.48 27.251 36.552 ;
     RECT  24.304 9.12 27.301 9.144 ;
     RECT  27.301 9.12 27.347 9.528 ;
     RECT  26.813 20.88 27.889 20.904 ;
     RECT  27.251 3.936 27.925 3.96 ;
     RECT  27.137 22.464 28.037 24.936 ;
     RECT  28.037 22.512 28.145 24.936 ;
     RECT  26.963 47.856 28.145 47.88 ;
     RECT  28.145 23.904 28.181 24.936 ;
     RECT  27.889 20.88 28.285 21.192 ;
     RECT  28.285 20.4 28.393 21.192 ;
     RECT  28.141 29.04 28.393 29.064 ;
     RECT  27.817 27.504 28.465 27.528 ;
     RECT  28.537 30.336 28.573 30.36 ;
     RECT  28.393 20.4 28.609 21.384 ;
     RECT  27.925 3.36 28.645 3.96 ;
     RECT  28.465 27.504 28.645 27.96 ;
     RECT  28.393 29.04 28.645 29.352 ;
     RECT  28.609 20.4 28.753 21.432 ;
     RECT  28.645 27.504 29.077 29.352 ;
     RECT  28.969 50.736 29.171 50.76 ;
     RECT  28.181 23.904 29.249 23.928 ;
     RECT  28.181 24.912 29.249 24.936 ;
     RECT  29.077 27.36 29.257 29.352 ;
     RECT  28.573 30.336 29.257 30.456 ;
     RECT  29.257 27.36 29.329 30.456 ;
     RECT  28.969 31.488 29.329 31.512 ;
     RECT  24.304 1.728 29.408 1.752 ;
     RECT  28.645 2.832 29.408 3.96 ;
     RECT  27.347 9.504 29.408 9.528 ;
     RECT  28.753 20.4 29.408 21.528 ;
     RECT  28.145 22.512 29.408 22.776 ;
     RECT  29.249 23.904 29.408 24.936 ;
     RECT  29.329 27.36 29.408 31.512 ;
     RECT  27.251 32.736 29.408 32.76 ;
     RECT  27.251 36.48 29.408 36.504 ;
     RECT  24.304 44.976 29.408 45 ;
     RECT  29.121 47.04 29.408 47.064 ;
     RECT  27.011 49.536 29.408 49.56 ;
     RECT  29.408 1.728 29.557 49.692 ;
     RECT  29.557 1.728 29.644 49.8 ;
     RECT  29.644 1.728 29.704 49.56 ;
     RECT  29.704 3.84 29.801 4.152 ;
     RECT  29.704 27.456 29.801 28.2 ;
     RECT  29.801 27.456 29.873 27.72 ;
     RECT  29.704 29.232 29.945 29.352 ;
     RECT  29.704 30.336 29.945 30.792 ;
     RECT  29.704 32.736 30.161 32.76 ;
     RECT  29.801 3.936 30.485 4.152 ;
     RECT  29.704 47.04 30.611 48.072 ;
     RECT  29.945 30.768 30.673 30.792 ;
     RECT  30.625 50.736 30.899 50.76 ;
     RECT  29.704 21.408 30.917 22.344 ;
     RECT  29.945 29.232 31.025 29.256 ;
     RECT  30.611 47.04 31.025 47.592 ;
     RECT  30.917 21.408 31.601 21.432 ;
     RECT  29.873 27.696 31.669 27.72 ;
     RECT  31.309 25.968 31.741 25.992 ;
     RECT  31.669 27.696 31.925 27.912 ;
     RECT  31.057 31.2 31.961 31.224 ;
     RECT  29.704 24.624 32.137 24.936 ;
     RECT  31.741 25.968 32.137 26.136 ;
     RECT  31.633 29.088 32.141 29.112 ;
     RECT  32.137 24.432 32.245 26.136 ;
     RECT  32.245 24.432 32.321 26.568 ;
     RECT  30.485 3.936 32.389 3.96 ;
     RECT  32.321 24.624 32.569 26.568 ;
     RECT  32.461 30.816 32.573 30.84 ;
     RECT  32.425 50.736 32.627 50.76 ;
     RECT  29.704 1.728 32.653 1.752 ;
     RECT  32.389 3.6 32.677 3.96 ;
     RECT  32.569 24.624 32.717 26.616 ;
     RECT  29.704 9.504 32.725 9.528 ;
     RECT  32.677 3.6 32.771 4.248 ;
     RECT  32.771 3.6 32.897 3.624 ;
     RECT  32.965 23.52 33.257 23.544 ;
     RECT  32.717 24.624 33.293 26.568 ;
     RECT  31.925 27.888 33.433 27.912 ;
     RECT  33.293 24.624 33.473 26.52 ;
     RECT  33.473 24.624 33.617 26.136 ;
     RECT  33.617 24.624 33.689 25.944 ;
     RECT  33.433 27.648 33.761 27.912 ;
     RECT  31.025 47.04 33.793 47.064 ;
     RECT  33.689 24.624 33.865 25.224 ;
     RECT  29.704 49.536 34.693 49.56 ;
     RECT  33.793 47.04 34.765 47.352 ;
     RECT  34.009 48.384 34.765 48.408 ;
     RECT  34.693 49.536 34.787 49.848 ;
     RECT  32.725 9.504 34.808 9.816 ;
     RECT  33.865 24.48 34.808 25.224 ;
     RECT  33.761 27.888 34.808 27.912 ;
     RECT  34.693 28.944 34.808 28.968 ;
     RECT  34.765 47.04 34.808 48.408 ;
     RECT  34.787 49.536 34.808 49.692 ;
     RECT  34.808 2.148 34.912 49.692 ;
     RECT  34.912 2.418 35.104 49.56 ;
     RECT  35.104 9.792 35.201 9.96 ;
     RECT  35.104 25.2 35.201 25.608 ;
     RECT  35.104 28.944 35.219 28.968 ;
     RECT  35.104 48.384 35.345 48.408 ;
     RECT  35.104 47.04 35.741 47.064 ;
     RECT  35.104 49.536 36.083 49.56 ;
     RECT  36.313 50.736 36.515 50.76 ;
     RECT  35.201 9.936 36.565 9.96 ;
     RECT  35.201 25.584 36.709 25.608 ;
     RECT  36.565 9.648 36.755 9.96 ;
     RECT  35.104 27.888 38.917 27.912 ;
     RECT  38.917 27.888 38.981 28.104 ;
     RECT  38.981 28.08 39.004 28.104 ;
     RECT  36.709 24.768 40.208 25.608 ;
     RECT  35.104 26.784 40.208 26.808 ;
     RECT  40.208 2.148 40.312 49.692 ;
     RECT  40.312 2.418 40.504 49.422 ;
     RECT  40.504 26.784 40.601 27.336 ;
     RECT  40.504 24.768 42.329 25.512 ;
     RECT  40.601 27.312 42.361 27.336 ;
     RECT  42.361 26.736 42.401 27.336 ;
     RECT  42.329 24.768 43.881 24.792 ;
     RECT  42.401 26.736 43.945 26.76 ;
     RECT  43.881 24.768 43.955 25.08 ;
     RECT  43.945 26.208 43.985 26.76 ;
     RECT  43.985 26.208 45.493 26.232 ;
     RECT  43.955 25.056 45.529 25.08 ;
     RECT  45.529 24.48 45.608 25.08 ;
     RECT  45.493 26.208 45.608 26.328 ;
     RECT  45.608 2.148 45.712 49.692 ;
     RECT  45.712 2.418 45.904 49.422 ;
     RECT  45.904 26.304 46.541 26.328 ;
     RECT  45.904 24.48 46.613 24.504 ;
     RECT  49.849 26.736 50.641 26.76 ;
     RECT  50.641 26.736 50.677 27.192 ;
     RECT  50.677 24.576 50.713 27.624 ;
     RECT  50.713 24.144 51.804 27.624 ;
    LAYER M5 ;
     RECT  19.2 0.016 32.616 1.763 ;
     RECT  2.4 2.137 2.52 2.151 ;
     RECT  7.8 2.137 7.92 2.151 ;
     RECT  13.2 2.137 13.32 2.151 ;
     RECT  34.8 2.137 34.92 2.151 ;
     RECT  40.2 2.137 40.32 2.151 ;
     RECT  45.6 2.137 45.72 2.151 ;
     RECT  29.4 1.763 29.712 2.821 ;
     RECT  28.656 2.821 29.712 3.587 ;
     RECT  2.4 2.151 2.712 9.061 ;
     RECT  27.216 4.837 27.24 9.109 ;
     RECT  27.216 9.109 27.336 9.155 ;
     RECT  27.312 9.155 27.336 9.539 ;
     RECT  32.736 4.213 32.76 9.827 ;
     RECT  2.4 9.061 3.288 10.595 ;
     RECT  7.8 2.151 8.112 10.693 ;
     RECT  7.44 10.693 8.112 10.789 ;
     RECT  5.088 11.221 5.112 11.941 ;
     RECT  7.44 10.789 9.096 12.035 ;
     RECT  5.088 11.941 6.312 12.803 ;
     RECT  5.328 12.803 6.312 13.859 ;
     RECT  5.328 13.859 5.352 14.773 ;
     RECT  7.8 12.035 9.096 15.205 ;
     RECT  7.584 15.205 9.096 15.349 ;
     RECT  4.848 14.773 5.352 15.971 ;
     RECT  7.44 15.349 9.096 16.019 ;
     RECT  4.896 15.971 5.352 16.405 ;
     RECT  4.896 16.405 5.688 16.547 ;
     RECT  7.584 16.019 9.096 17.509 ;
     RECT  4.896 16.547 5.4 17.651 ;
     RECT  7.488 17.509 9.096 18.851 ;
     RECT  7.584 18.851 9.096 19.091 ;
     RECT  5.088 17.651 5.4 19.379 ;
     RECT  5.376 19.379 5.4 20.003 ;
     RECT  29.4 3.587 29.712 21.445 ;
     RECT  24 1.763 24.312 22.021 ;
     RECT  26.592 20.869 26.616 22.021 ;
     RECT  21.888 3.157 21.912 22.067 ;
     RECT  26.592 22.021 26.712 22.067 ;
     RECT  26.688 22.067 26.712 22.163 ;
     RECT  24 22.021 25.08 22.597 ;
     RECT  4.896 21.397 4.92 22.835 ;
     RECT  29.28 21.445 29.712 23.987 ;
     RECT  26.832 22.981 26.856 24.467 ;
     RECT  34.8 2.151 35.112 24.469 ;
     RECT  29.4 23.987 29.712 24.613 ;
     RECT  36.72 9.637 36.744 24.803 ;
     RECT  4.848 23.317 4.872 24.947 ;
     RECT  43.92 24.757 43.944 25.091 ;
     RECT  24 22.597 25.176 25.139 ;
     RECT  34.176 24.469 35.112 25.235 ;
     RECT  20.304 16.789 20.328 26.197 ;
     RECT  20.16 26.197 20.328 26.243 ;
     RECT  5.904 25.189 5.928 26.485 ;
     RECT  34.8 25.235 35.112 26.773 ;
     RECT  7.584 19.091 8.952 26.869 ;
     RECT  7.584 26.869 9.096 27.107 ;
     RECT  24 25.139 24.408 27.635 ;
     RECT  29.4 24.613 30.648 27.685 ;
     RECT  5.904 26.485 5.976 27.877 ;
     RECT  5.904 27.877 6.792 27.923 ;
     RECT  38.928 26.773 38.952 28.115 ;
     RECT  2.4 10.595 2.712 28.405 ;
     RECT  5.952 27.923 6.792 28.547 ;
     RECT  34.8 26.773 35.208 28.979 ;
     RECT  4.512 27.877 4.536 29.699 ;
     RECT  5.952 28.547 5.976 30.661 ;
     RECT  7.8 27.107 9.096 30.661 ;
     RECT  2.4 28.405 3.288 30.709 ;
     RECT  7.632 30.661 9.096 30.803 ;
     RECT  29.28 27.685 30.648 30.803 ;
     RECT  5.952 30.661 6.504 31.907 ;
     RECT  7.8 30.803 9.096 32.531 ;
     RECT  2.4 30.709 3.336 32.771 ;
     RECT  7.8 32.531 8.52 33.013 ;
     RECT  6.192 31.907 6.504 33.059 ;
     RECT  4.848 33.637 4.872 34.787 ;
     RECT  22.128 24.469 22.152 35.317 ;
     RECT  20.16 26.243 20.184 35.411 ;
     RECT  7.68 33.013 8.52 35.845 ;
     RECT  29.28 30.803 29.712 36.469 ;
     RECT  21.648 35.317 22.152 36.563 ;
     RECT  27.216 31.141 27.24 36.563 ;
     RECT  7.68 35.845 8.664 38.387 ;
     RECT  7.8 38.387 8.664 39.781 ;
     RECT  4.224 38.629 4.248 40.307 ;
     RECT  7.392 39.781 8.664 41.075 ;
     RECT  7.8 41.075 8.664 41.749 ;
     RECT  4.848 40.981 4.872 42.227 ;
     RECT  7.8 41.749 9.096 43.573 ;
     RECT  6.192 33.059 6.216 44.579 ;
     RECT  18.6 2.137 18.912 44.965 ;
     RECT  29.088 36.469 29.712 45.011 ;
     RECT  7.2 43.573 9.096 46.787 ;
     RECT  21.024 46.117 21.048 46.789 ;
     RECT  22.128 36.563 22.152 46.789 ;
     RECT  10.608 46.741 10.632 46.883 ;
     RECT  29.184 45.011 29.712 47.075 ;
     RECT  21.024 46.789 22.152 47.173 ;
     RECT  7.2 46.787 8.232 47.363 ;
     RECT  26.928 37.573 26.952 47.363 ;
     RECT  7.2 47.363 8.112 47.411 ;
     RECT  29.4 47.075 29.712 47.557 ;
     RECT  21.024 47.173 22.2 47.891 ;
     RECT  29.4 47.557 30.6 48.083 ;
     RECT  16.512 47.221 16.536 48.515 ;
     RECT  18.6 44.965 19.464 48.515 ;
     RECT  26.976 48.997 27 49.333 ;
     RECT  26.112 49.333 27 49.477 ;
     RECT  15.312 26.005 15.336 49.525 ;
     RECT  16.608 49.477 16.632 49.525 ;
     RECT  18.6 48.515 18.912 49.525 ;
     RECT  21.888 47.891 22.2 49.525 ;
     RECT  24 27.635 24.312 49.525 ;
     RECT  25.68 49.477 27 49.525 ;
     RECT  29.4 48.083 29.712 49.525 ;
     RECT  34.8 28.979 35.112 49.525 ;
     RECT  2.4 32.771 2.712 49.689 ;
     RECT  7.8 47.411 8.112 49.689 ;
     RECT  13.2 2.151 13.512 49.689 ;
     RECT  40.2 2.151 40.512 49.689 ;
     RECT  45.6 2.151 45.912 49.689 ;
     RECT  2.4 49.689 2.52 49.703 ;
     RECT  7.8 49.689 7.92 49.703 ;
     RECT  13.2 49.689 13.32 49.703 ;
     RECT  40.2 49.689 40.32 49.703 ;
     RECT  45.6 49.689 45.72 49.703 ;
     RECT  15.312 49.525 36.072 50.725 ;
     RECT  15.312 50.725 36.504 51.792 ;
     RECT  21.888 1.763 21.912 3.157 ;
     RECT  28.656 1.763 29.4 2.821 ;
     RECT  6.312 11.941 7.44 12.035 ;
     RECT  6.312 12.035 7.8 13.859 ;
     RECT  7.44 13.859 7.8 15.205 ;
     RECT  7.44 15.205 7.584 15.349 ;
     RECT  7.488 16.019 7.584 17.509 ;
     RECT  18.912 16.789 20.304 26.197 ;
     RECT  25.08 22.021 26.592 22.067 ;
     RECT  25.08 22.067 26.688 22.163 ;
     RECT  25.08 22.163 25.176 22.597 ;
     RECT  18.912 26.197 20.16 35.411 ;
     RECT  38.952 26.773 40.2 28.115 ;
     RECT  7.584 27.107 7.8 27.877 ;
     RECT  4.536 27.877 5.904 27.923 ;
     RECT  6.792 27.877 7.8 28.547 ;
     RECT  4.536 27.923 5.952 29.699 ;
     RECT  3.288 28.405 4.512 29.699 ;
     RECT  3.288 29.699 3.336 30.709 ;
     RECT  6.504 30.661 7.632 30.803 ;
     RECT  6.504 30.803 7.8 33.013 ;
     RECT  6.504 33.013 7.68 33.059 ;
     RECT  6.216 33.059 7.68 38.387 ;
     RECT  4.872 33.637 6.192 34.787 ;
     RECT  20.184 35.317 21.648 35.411 ;
     RECT  6.216 38.387 7.8 39.781 ;
     RECT  2.712 38.629 4.224 40.307 ;
     RECT  6.216 39.781 7.392 41.075 ;
     RECT  4.872 40.981 6.192 42.227 ;
     RECT  6.216 43.573 7.2 44.579 ;
     RECT  21.048 46.117 22.128 46.789 ;
     RECT  9.096 46.741 10.608 46.787 ;
     RECT  15.336 47.221 16.512 48.515 ;
     RECT  29.712 48.083 30.6 49.525 ;
     RECT  15.336 48.515 16.536 49.477 ;
     RECT  18.912 48.515 19.464 49.525 ;
     RECT  15.336 49.477 16.608 49.525 ;
     RECT  24.312 49.477 25.68 49.525 ;
  END
END dsfd_vm_static_read_v0_p
END LIBRARY
